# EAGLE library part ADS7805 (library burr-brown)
16-Bit 10us Sampling CMOS ADC

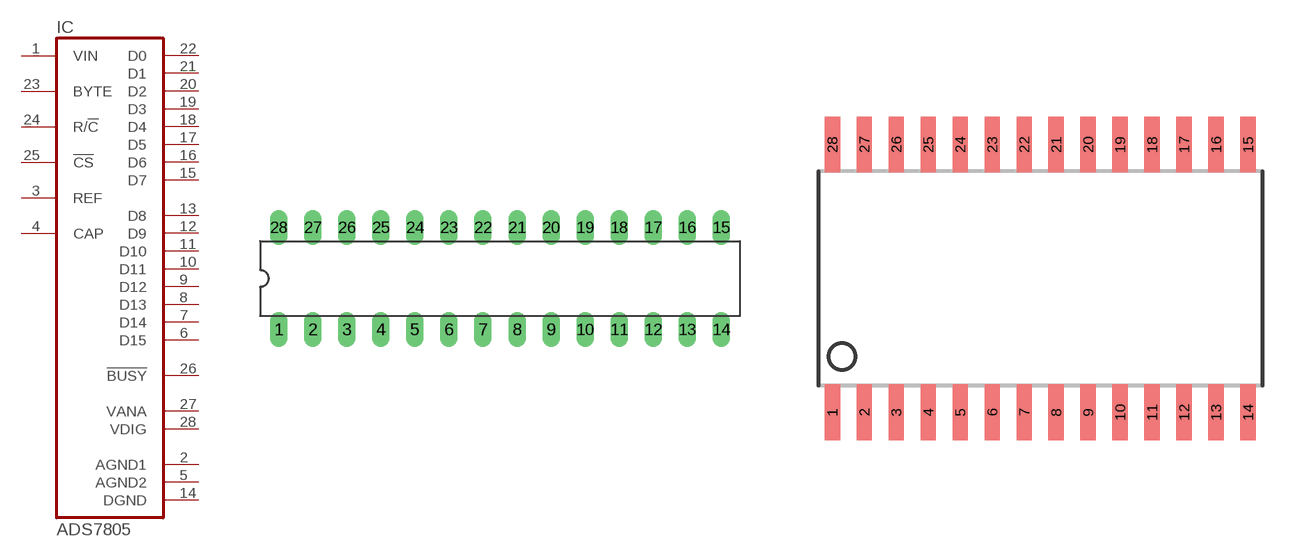
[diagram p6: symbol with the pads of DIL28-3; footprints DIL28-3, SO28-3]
Designator prefix IC

## ADS7805P (MF: TEXAS INSTRUMENTS; MPN: ADS7805P; OC_FARNELL: 1212283; OC_NEWARK: 35C1528)  [DIL28-3]
1  VIN  in
2  AGND1  pwr
3  REF
4  CAP  pas
5  AGND2  pwr
6  D15  out
7  D14  out
8  D13  out
9  D12  out
10  D11  out
11  D10  out
12  D9  out
13  D8  out
14  DGND  pwr
15  D7  out
16  D6  out
17  D5  out
18  D4  out
19  D3  out
20  D2  out
21  D1  out
22  D0  out
23  BYTE  in
24  R/!C  in
25  !CS  in
26  !BUSY  out
27  VANA  pwr
28  VDIG  pwr

## ADS7805U (MF: TEXAS INSTRUMENTS; MPN: ADS7805U; OC_FARNELL: 1192284; OC_NEWARK: 80K5546)  [SO28-3]
Pads as for DIL28-3

## Footprint DIL28-3 (pad centres in mm)
Dual In Line 0.3 inch
drill 0.813 long: 1 -16.51,-3.81; 2 -13.97,-3.81; 3 -11.43,-3.81; 4 -8.89,-3.81; 5 -6.35,-3.81; 6 -3.81,-3.81; 7 -1.27,-3.81; 8 1.27,-3.81; 9 3.81,-3.81; 10 6.35,-3.81; 11 8.89,-3.81; 12 11.43,-3.81; 13 13.97,-3.81; 14 16.51,-3.81; 15 16.51,3.81; 16 13.97,3.81; 17 11.43,3.81; 18 8.89,3.81; 19 6.35,3.81; 20 3.81,3.81; 21 1.27,3.81; 22 -1.27,3.81; 23 -3.81,3.81; 24 -6.35,3.81; 25 -8.89,3.81; 26 -11.43,3.81; 27 -13.97,3.81; 28 -16.51,3.81

## Footprint SO28-3 (pad centres in mm)
Small Outline Package
smd 0.61 x 2.21: 1 -8.255,-5.315; 2 -6.985,-5.315; 3 -5.715,-5.315; 4 -4.445,-5.315; 5 -3.175,-5.315; 6 -1.905,-5.315; 7 -0.635,-5.315; 8 0.635,-5.315; 9 1.905,-5.315; 10 3.175,-5.315; 11 4.445,-5.315; 12 5.715,-5.315; 13 6.985,-5.315; 14 8.255,-5.315; 15 8.255,5.315; 16 6.985,5.315; 17 5.715,5.315; 18 4.445,5.315; 19 3.175,5.315; 20 1.905,5.315; 21 0.635,5.315; 22 -0.635,5.315; 23 -1.905,5.315; 24 -3.175,5.315; 25 -4.445,5.315; 26 -5.715,5.315; 27 -6.985,5.315; 28 -8.255,5.315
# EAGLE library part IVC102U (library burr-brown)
Amplifier Precision Switched Integrator Transimpedance

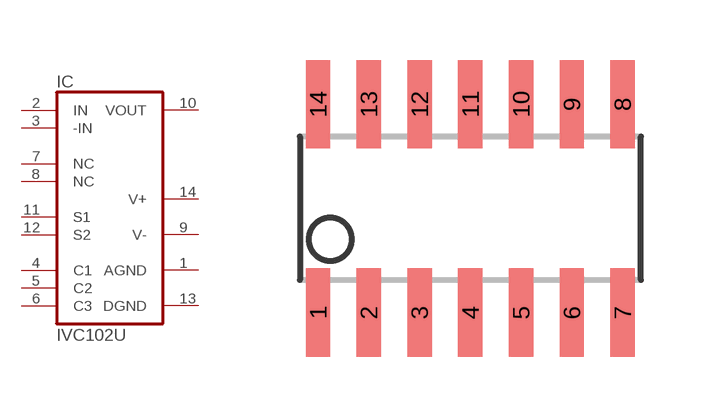
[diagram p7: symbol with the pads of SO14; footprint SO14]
Designator prefix IC

## IVC102U (MPN: IVC102U; OC_FARNELL: 1212427; OC_NEWARK: 03P0868)  [SO14]
1  AGND  pwr
2  IN  in
3  -IN  in
4  C1  pas
5  C2  pas
6  C3  pas
7  NC  nc
8  NC  nc
9  V-  pwr
10  VOUT  out
11  S1  in
12  S2  in
13  DGND  pwr
14  V+  pwr

## Footprint SO14 (pad centres in mm)
Small Outline Package
smd 0.61 x 2.21: 1 -3.81,-2.603; 2 -2.54,-2.603; 3 -1.27,-2.603; 4 0,-2.603; 5 1.27,-2.603; 6 2.54,-2.603; 7 3.81,-2.603; 8 3.81,2.603; 9 2.54,2.603; 10 1.27,2.603; 11 0,2.603; 12 -1.27,2.603; 13 -2.54,2.603; 14 -3.81,2.603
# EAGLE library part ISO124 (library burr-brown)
Isolation Amplifier Precision, Lowest Cost

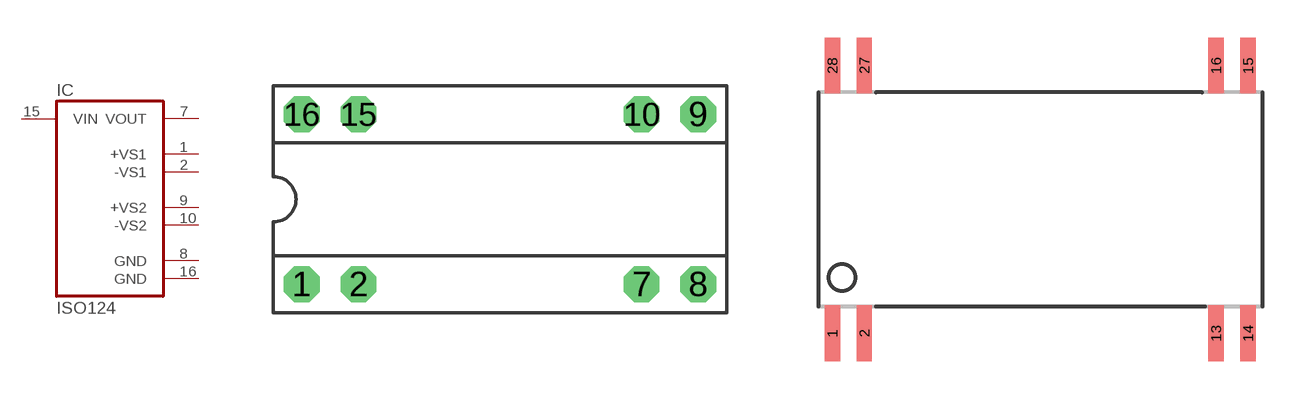
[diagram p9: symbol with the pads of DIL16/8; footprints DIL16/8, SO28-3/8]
Designator prefix IC

## ISO124P (MF: TEXAS INSTRUMENTS; MPN: ISO124P; OC_FARNELL: 1212425; OC_NEWARK: 35C1752)  [DIL16/8]
1  +VS1  pwr
2  -VS1  pwr
7  VOUT  out
8  GND  pwr
9  +VS2  pwr
10  -VS2  pwr
15  VIN  in
16  GND  pwr

## ISO124U (MF: TEXAS INSTRUMENTS; MPN: ISO124U; OC_FARNELL: 1212426; OC_NEWARK: 10M8426)  [SO28-3/8]
1  +VS1  pwr
2  -VS1  pwr
13  VOUT  out
14  GND  pwr
15  +VS2  pwr
16  -VS2  pwr
27  VIN  in
28  GND  pwr

## Footprint DIL16/8 (pad centres in mm)
Dual In Line
drill 0.813 pad 1.6 octagon: 1 -8.89,-3.81; 2 -6.35,-3.81; 7 6.35,-3.81; 8 8.89,-3.81; 9 8.89,3.81; 10 6.35,3.81; 15 -6.35,3.81; 16 -8.89,3.81

## Footprint SO28-3/8 (pad centres in mm)
Small Outline Package
smd 0.61 x 2.21: 1 -8.255,-5.315; 2 -6.985,-5.315; 13 6.985,-5.315; 14 8.255,-5.315; 15 8.255,5.315; 16 6.985,5.315; 27 -6.985,5.315; 28 -8.255,5.315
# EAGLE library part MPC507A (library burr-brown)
CMOS Analog Multiplexers Single-Ended 16-Channel/Differential 8-Channel

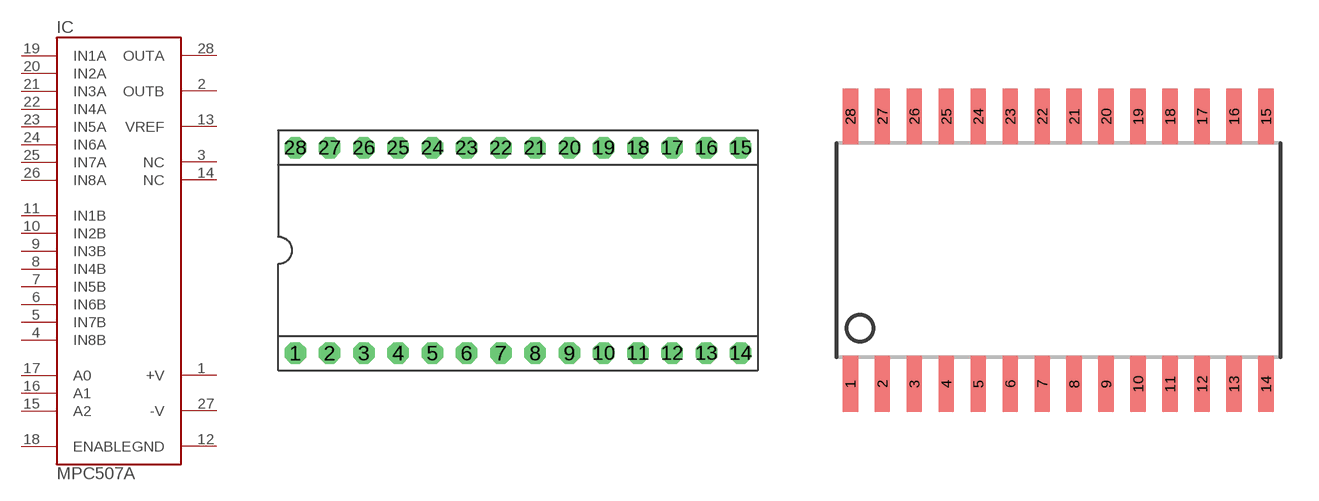
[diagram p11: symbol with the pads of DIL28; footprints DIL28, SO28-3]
Designator prefix IC

## MPC507AP (MF: TEXAS INSTRUMENTS; MPN: MPC507AP; OC_FARNELL: 1648762; OC_NEWARK: 75C3662)  [DIL28]
1  +V  pwr
2  OUTB  out
3  NC  nc
4  IN8B  in
5  IN7B  in
6  IN6B  in
7  IN5B  in
8  IN4B  in
9  IN3B  in
10  IN2B  in
11  IN1B  in
12  GND  pwr
13  VREF
14  NC  nc
15  A2  in
16  A1  in
17  A0  in
18  ENABLE  in
19  IN1A  in
20  IN2A  in
21  IN3A  in
22  IN4A  in
23  IN5A  in
24  IN6A  in
25  IN7A  in
26  IN8A  in
27  -V  pwr
28  OUTA  out

## MPC507AU (MF: TEXAS INSTRUMENTS; MPN: MPC507AU; OC_FARNELL: 1577157; OC_NEWARK: 75C3663)  [SO28-3]
Pads as for DIL28

## Footprint DIL28 (pad centres in mm)
Dual In Line
drill 0.813 pad 1.6 octagon: 1 -16.51,-7.62; 2 -13.97,-7.62; 3 -11.43,-7.62; 4 -8.89,-7.62; 5 -6.35,-7.62; 6 -3.81,-7.62; 7 -1.27,-7.62; 8 1.27,-7.62; 9 3.81,-7.62; 10 6.35,-7.62; 11 8.89,-7.62; 12 11.43,-7.62; 13 13.97,-7.62; 14 16.51,-7.62; 15 16.51,7.62; 16 13.97,7.62; 17 11.43,7.62; 18 8.89,7.62; 19 6.35,7.62; 20 3.81,7.62; 21 1.27,7.62; 22 -1.27,7.62; 23 -3.81,7.62; 24 -6.35,7.62; 25 -8.89,7.62; 26 -11.43,7.62; 27 -13.97,7.62; 28 -16.51,7.62

## Footprint SO28-3 (pad centres in mm)
Small Outline Package
smd 0.61 x 2.21: 1 -8.255,-5.315; 2 -6.985,-5.315; 3 -5.715,-5.315; 4 -4.445,-5.315; 5 -3.175,-5.315; 6 -1.905,-5.315; 7 -0.635,-5.315; 8 0.635,-5.315; 9 1.905,-5.315; 10 3.175,-5.315; 11 4.445,-5.315; 12 5.715,-5.315; 13 6.985,-5.315; 14 8.255,-5.315; 15 8.255,5.315; 16 6.985,5.315; 17 5.715,5.315; 18 4.445,5.315; 19 3.175,5.315; 20 1.905,5.315; 21 0.635,5.315; 22 -0.635,5.315; 23 -1.905,5.315; 24 -3.175,5.315; 25 -4.445,5.315; 26 -5.715,5.315; 27 -6.985,5.315; 28 -8.255,5.315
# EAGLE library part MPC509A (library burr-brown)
CMOS Analog Multiplexers Single-Ended 8-Channel/Differential 4-Channel

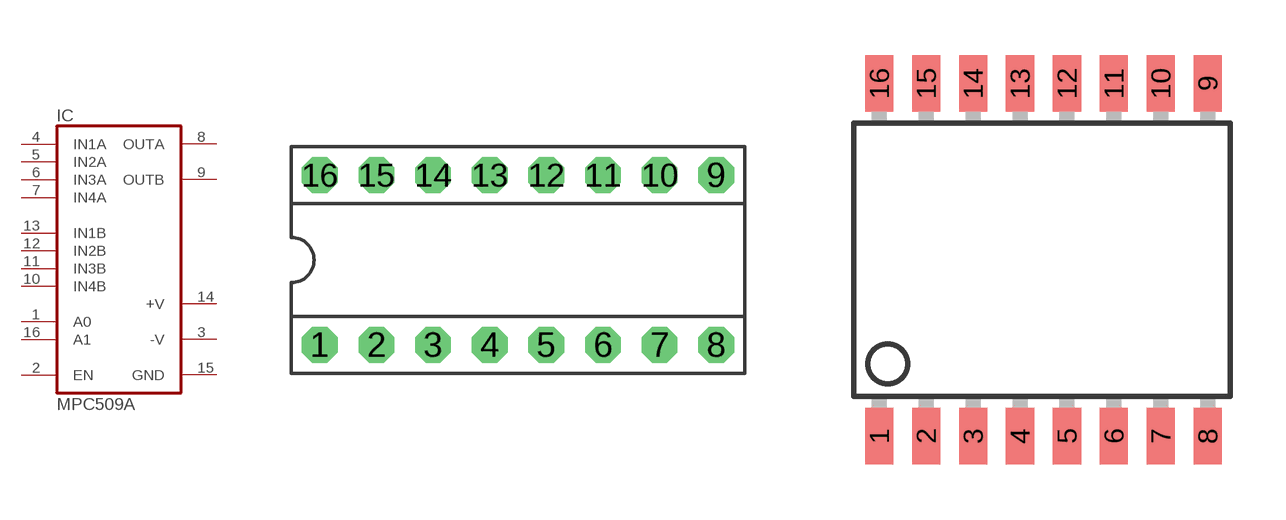
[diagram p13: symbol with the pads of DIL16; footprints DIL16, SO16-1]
Designator prefix IC

## MPC509AP (MF: TEXAS INSTRUMENT CONNECTORS; MPN: MPC509AP; OC_FARNELL: 1214449; OC_NEWARK: 75C3667)  [DIL16]
1  A0  in
2  EN  in
3  -V  pwr
4  IN1A  in
5  IN2A  in
6  IN3A  in
7  IN4A  in
8  OUTA  out
9  OUTB  out
10  IN4B  in
11  IN3B  in
12  IN2B  in
13  IN1B  in
14  +V  pwr
15  GND  pwr
16  A1  in

## MPC509AU (MPN: MPC509AUG4; OC_FARNELL: 1206921; OC_NEWARK: 97K5354)  [SO16-1]
Pads as for DIL16

## Footprint DIL16 (pad centres in mm)
Dual In Line
drill 0.813 pad 1.6 octagon: 1 -8.89,-3.81; 2 -6.35,-3.81; 3 -3.81,-3.81; 4 -1.27,-3.81; 5 1.27,-3.81; 6 3.81,-3.81; 7 6.35,-3.81; 8 8.89,-3.81; 9 8.89,3.81; 10 6.35,3.81; 11 3.81,3.81; 12 1.27,3.81; 13 -1.27,3.81; 14 -3.81,3.81; 15 -6.35,3.81; 16 -8.89,3.81

## Footprint SO16-1 (pad centres in mm)
Small Outline Package
smd 0.762 x 1.524: 1 -4.445,-4.775; 2 -3.175,-4.775; 3 -1.905,-4.775; 4 -0.635,-4.775; 5 0.635,-4.775; 6 1.905,-4.775; 7 3.175,-4.775; 8 4.445,-4.775; 9 4.445,4.775; 10 3.175,4.775; 11 1.905,4.775; 12 0.635,4.775; 13 -0.635,4.775; 14 -1.905,4.775; 15 -3.175,4.775; 16 -4.445,4.775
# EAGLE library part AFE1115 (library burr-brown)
HDSL/MDSL Analog Front End with VCXO

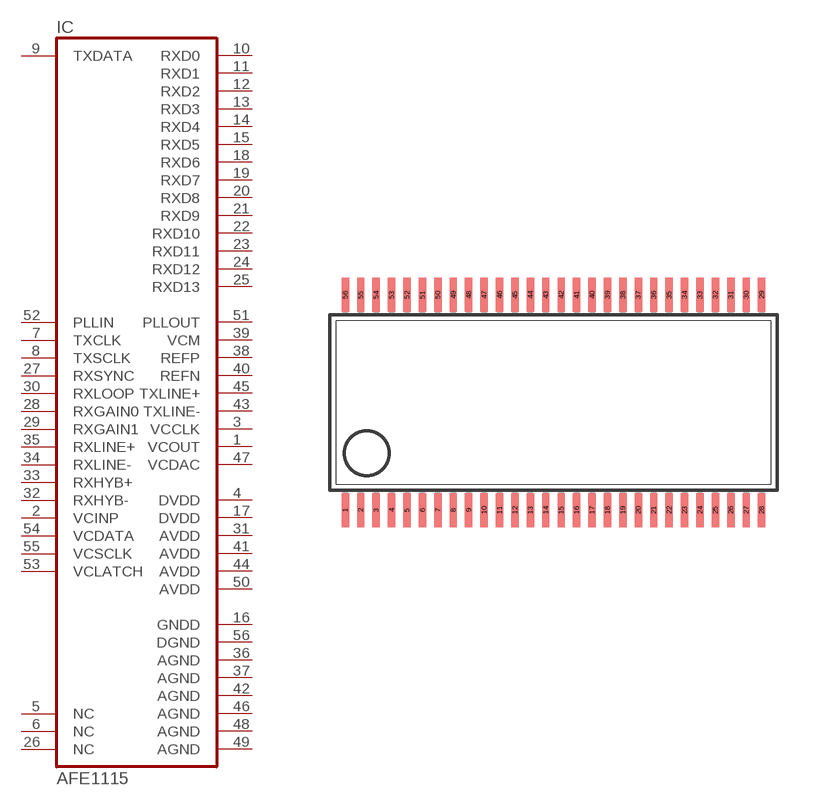
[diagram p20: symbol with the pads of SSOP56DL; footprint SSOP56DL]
Designator prefix IC

## AFE1115E (OC_FARNELL: unknown; OC_NEWARK: unknown)  [SSOP56DL]
1  VCOUT  out
2  VCINP  in
3  VCCLK  out
4  DVDD  pwr
5  NC  nc
6  NC  nc
7  TXCLK  in
8  TXSCLK  in
9  TXDATA  in
10  RXD0  out
11  RXD1  out
12  RXD2  out
13  RXD3  out
14  RXD4  out
15  RXD5  out
16  GNDD  pwr
17  DVDD  pwr
18  RXD6  out
19  RXD7  out
20  RXD8  out
21  RXD9  out
22  RXD10  out
23  RXD11  out
24  RXD12  out
25  RXD13  out
26  NC  nc
27  RXSYNC  in
28  RXGAIN0  in
29  RXGAIN1  in
30  RXLOOP  in
31  AVDD  pwr
32  RXHYB-  in
33  RXHYB+  in
34  RXLINE-  in
35  RXLINE+  in
36  AGND  pwr
37  AGND  pwr
38  REFP  out
39  VCM  out
40  REFN  out
41  AVDD  pwr
42  AGND  pwr
43  TXLINE-  out
44  AVDD  pwr
45  TXLINE+  out
46  AGND  pwr
47  VCDAC  out
48  AGND  pwr
49  AGND  out
50  AVDD  pwr
51  PLLOUT  out
52  PLLIN  in
53  VCLATCH  in
54  VCDATA  in
55  VCSCLK  in
56  DGND  pwr

## Footprint SSOP56DL (pad centres in mm)
Small Shrink Outline Package
smd 0.305 x 1.397: 1 -8.572,-4.432; 2 -7.938,-4.432; 3 -7.303,-4.432; 4 -6.668,-4.432; 5 -6.032,-4.432; 6 -5.397,-4.432; 7 -4.763,-4.432; 8 -4.128,-4.432; 9 -3.493,-4.432; 10 -2.857,-4.432; 11 -2.223,-4.432; 12 -1.587,-4.432; 13 -0.953,-4.432; 14 -0.318,-4.432; 15 0.318,-4.432; 16 0.953,-4.432; 17 1.587,-4.432; 18 2.223,-4.432; 19 2.857,-4.432; 20 3.493,-4.432; 21 4.128,-4.432; 22 4.763,-4.432; 23 5.397,-4.432; 24 6.032,-4.432; 25 6.668,-4.432; 26 7.303,-4.432; 27 7.938,-4.432; 28 8.572,-4.432; 29 8.572,4.432; 30 7.938,4.432; 31 7.303,4.432; 32 6.668,4.432; 33 6.032,4.432; 34 5.397,4.432; 35 4.763,4.432; 36 4.128,4.432; 37 3.493,4.432; 38 2.857,4.432; 39 2.223,4.432; 40 1.587,4.432; 41 0.953,4.432; 42 0.318,4.432; 43 -0.318,4.432; 44 -0.953,4.432; 45 -1.587,4.432; 46 -2.223,4.432; 47 -2.857,4.432; 48 -3.493,4.432; 49 -4.128,4.432; 50 -4.763,4.432; 51 -5.397,4.432; 52 -6.032,4.432; 53 -6.668,4.432; 54 -7.303,4.432; 55 -7.938,4.432; 56 -8.572,4.432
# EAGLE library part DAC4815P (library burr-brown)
Quad 12-Bit DAC 8-Bit Port Interface

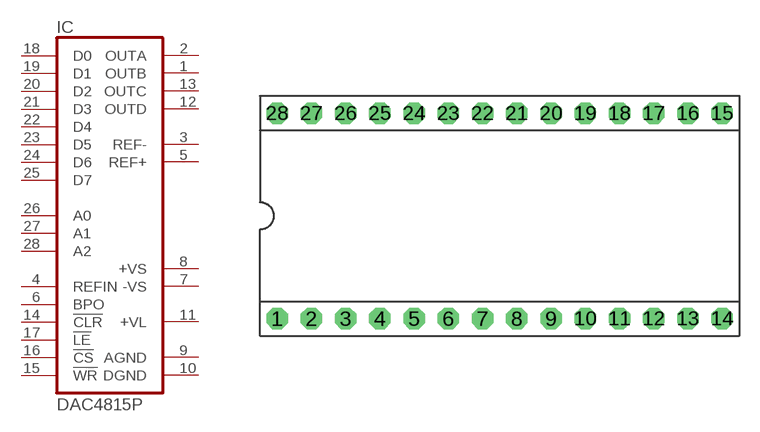
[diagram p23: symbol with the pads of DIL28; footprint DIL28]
Designator prefix IC

## DAC4815PP (OC_FARNELL: unknown; OC_NEWARK: unknown)  [DIL28]
1  OUTB  out
2  OUTA  out
3  REF-  out
4  REFIN  in
5  REF+  out
6  BPO  in
7  -VS  pwr
8  +VS  pwr
9  AGND  pwr
10  DGND  pwr
11  +VL  pwr
12  OUTD  out
13  OUTC  out
14  !CLR  in
15  !WR  in
16  !CS  in
17  !LE  in
18  D0  in
19  D1  in
20  D2  in
21  D3  in
22  D4  in
23  D5  in
24  D6  in
25  D7  in
26  A0  in
27  A1  in
28  A2  in

## Footprint DIL28 (pad centres in mm)
Dual In Line
drill 0.813 pad 1.6 octagon: 1 -16.51,-7.62; 2 -13.97,-7.62; 3 -11.43,-7.62; 4 -8.89,-7.62; 5 -6.35,-7.62; 6 -3.81,-7.62; 7 -1.27,-7.62; 8 1.27,-7.62; 9 3.81,-7.62; 10 6.35,-7.62; 11 8.89,-7.62; 12 11.43,-7.62; 13 13.97,-7.62; 14 16.51,-7.62; 15 16.51,7.62; 16 13.97,7.62; 17 11.43,7.62; 18 8.89,7.62; 19 6.35,7.62; 20 3.81,7.62; 21 1.27,7.62; 22 -1.27,7.62; 23 -3.81,7.62; 24 -6.35,7.62; 25 -8.89,7.62; 26 -11.43,7.62; 27 -13.97,7.62; 28 -16.51,7.62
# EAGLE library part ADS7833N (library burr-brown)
10-Channel, 12-Bit Data Acquisition System three synchronized A/D converters and seven S/H amplifiers

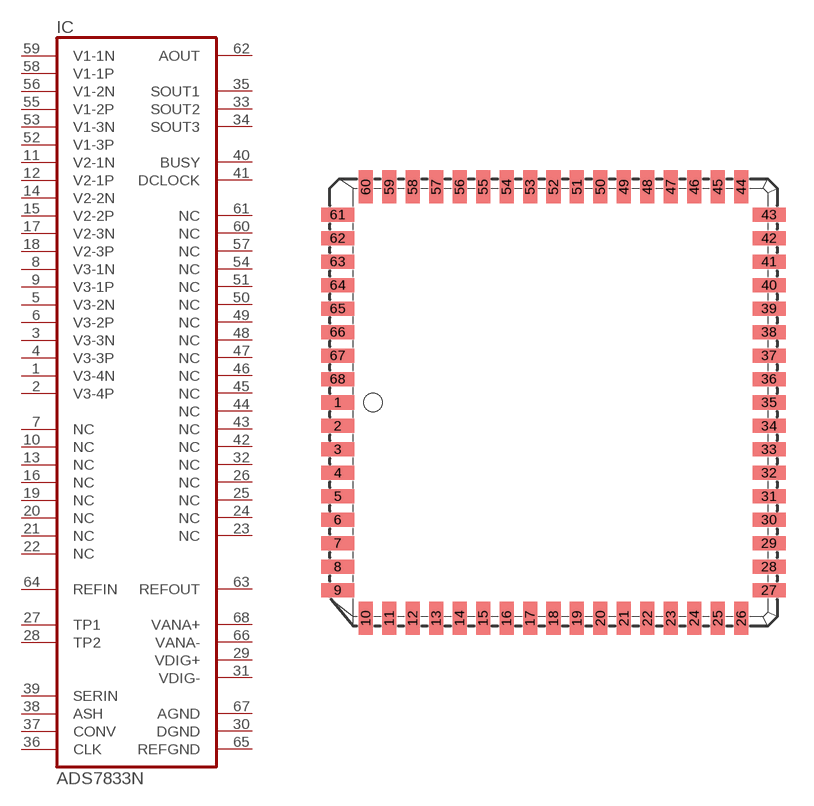
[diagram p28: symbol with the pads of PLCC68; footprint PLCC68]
Designator prefix IC

## ADS7833N (OC_FARNELL: unknown; OC_NEWARK: unknown)  [PLCC68]
1  V3-4N  in
2  V3-4P  in
3  V3-3N  in
4  V3-3P  in
5  V3-2N  in
6  V3-2P  in
7  NC  nc
8  V3-1N  in
9  V3-1P  in
10  NC  nc
11  V2-1N  in
12  V2-1P  in
13  NC  nc
14  V2-2N  in
15  V2-2P  in
16  NC  nc
17  V2-3N  in
18  V2-3P  in
19  NC  nc
20  NC  nc
21  NC  nc
22  NC  nc
23  NC  nc
24  NC  nc
25  NC  nc
26  NC  nc
27  TP1  pas
28  TP2  pas
29  VDIG+  pwr
30  DGND  pwr
31  VDIG-  pwr
32  NC  nc
33  SOUT2  out
34  SOUT3  out
35  SOUT1  out
36  CLK  in
37  CONV  in
38  ASH  in
39  SERIN  in
40  BUSY  out
41  DCLOCK  out
42  NC  nc
43  NC  nc
44  NC  nc
45  NC  nc
46  NC  nc
47  NC  nc
48  NC  nc
49  NC  nc
50  NC  nc
51  NC  nc
52  V1-3P  in
53  V1-3N  in
54  NC  nc
55  V1-2P  in
56  V1-2N  in
57  NC  nc
58  V1-1P  in
59  V1-1N  in
60  NC  nc
61  NC  nc
62  AOUT  out
63  REFOUT  out
64  REFIN  in
65  REFGND  pwr
66  VANA-  pwr
67  AGND  pwr
68  VANA+  pwr

## Footprint PLCC68 (pad centres in mm)
PLASTIC LEADED CHIP CARRIER square
smd 1.8 x 0.76: 1 -11.67,0; 2 -11.67,-1.27; 3 -11.67,-2.54; 4 -11.67,-3.81; 5 -11.67,-5.08; 6 -11.67,-6.35; 7 -11.67,-7.62; 8 -11.67,-8.89; 9 -11.67,-10.16; 27 11.67,-10.16; 28 11.67,-8.89; 29 11.67,-7.62; 30 11.67,-6.35; 31 11.67,-5.08; 32 11.67,-3.81; 33 11.67,-2.54; 34 11.67,-1.27; 35 11.67,0; 36 11.67,1.27; 37 11.67,2.54; 38 11.67,3.81; 39 11.67,5.08; 40 11.67,6.35; 41 11.67,7.62; 42 11.67,8.89; 43 11.67,10.16; 61 -11.67,10.16; 62 -11.67,8.89; 63 -11.67,7.62; 64 -11.67,6.35; 65 -11.67,5.08; 66 -11.67,3.81; 67 -11.67,2.54; 68 -11.67,1.27
smd 0.76 x 1.8: 10 -10.16,-11.67; 11 -8.89,-11.67; 12 -7.62,-11.67; 13 -6.35,-11.67; 14 -5.08,-11.67; 15 -3.81,-11.67; 16 -2.54,-11.67; 17 -1.27,-11.67; 18 0,-11.67; 19 1.27,-11.67; 20 2.54,-11.67; 21 3.81,-11.67; 22 5.08,-11.67; 23 6.35,-11.67; 24 7.62,-11.67; 25 8.89,-11.67; 26 10.16,-11.67; 44 10.16,11.67; 45 8.89,11.67; 46 7.62,11.67; 47 6.35,11.67; 48 5.08,11.67; 49 3.81,11.67; 50 2.54,11.67; 51 1.27,11.67; 52 0,11.67; 53 -1.27,11.67; 54 -2.54,11.67; 55 -3.81,11.67; 56 -5.08,11.67; 57 -6.35,11.67; 58 -7.62,11.67; 59 -8.89,11.67; 60 -10.16,11.67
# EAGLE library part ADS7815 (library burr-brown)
16-Bit 250kHz Sampling CMOS ADC

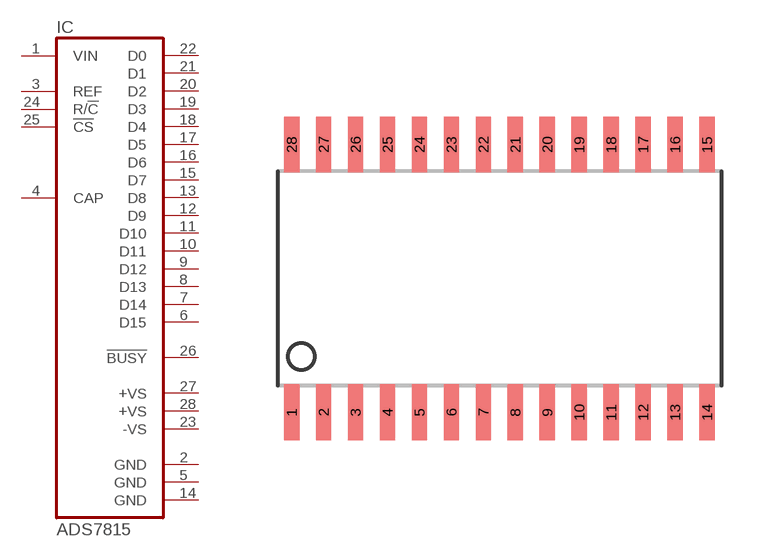
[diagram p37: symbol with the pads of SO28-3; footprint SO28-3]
Designator prefix IC

## ADS7815U (MPN: ADS7815UE4; OC_FARNELL: 1206867; OC_NEWARK: 96K6229)  [SO28-3]
1  VIN  in
2  GND  pwr
3  REF
4  CAP  pas
5  GND  pwr
6  D15  pwr
7  D14  pwr
8  D13  pwr
9  D12  pwr
10  D11  out
11  D10  out
12  D9  out
13  D8  out
14  GND  pwr
15  D7  out
16  D6  out
17  D5  out
18  D4  out
19  D3  out
20  D2  out
21  D1  out
22  D0  out
23  -VS  pwr
24  R/!C  in
25  !CS  in
26  !BUSY  out
27  +VS  pwr
28  +VS  pwr

## Footprint SO28-3 (pad centres in mm)
Small Outline Package
smd 0.61 x 2.21: 1 -8.255,-5.315; 2 -6.985,-5.315; 3 -5.715,-5.315; 4 -4.445,-5.315; 5 -3.175,-5.315; 6 -1.905,-5.315; 7 -0.635,-5.315; 8 0.635,-5.315; 9 1.905,-5.315; 10 3.175,-5.315; 11 4.445,-5.315; 12 5.715,-5.315; 13 6.985,-5.315; 14 8.255,-5.315; 15 8.255,5.315; 16 6.985,5.315; 17 5.715,5.315; 18 4.445,5.315; 19 3.175,5.315; 20 1.905,5.315; 21 0.635,5.315; 22 -0.635,5.315; 23 -1.905,5.315; 24 -3.175,5.315; 25 -4.445,5.315; 26 -5.715,5.315; 27 -6.985,5.315; 28 -8.255,5.315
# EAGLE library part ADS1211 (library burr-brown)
24-Bit Analog-to-Digital Converter

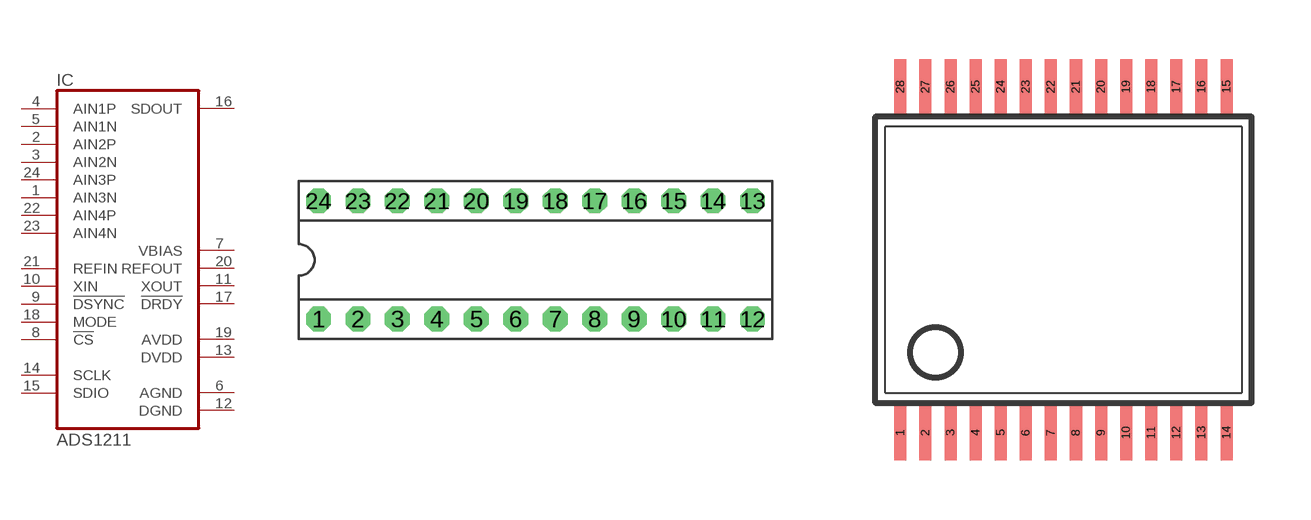
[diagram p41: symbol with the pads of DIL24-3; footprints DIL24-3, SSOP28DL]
Designator prefix IC

## ADS1211P (MF: TEXAS INSTRUMENTS; MPN: ADS1211P; OC_FARNELL: 1219430; OC_NEWARK: 96K2329)  [DIL24-3]
1  AIN3N  in
2  AIN2P  in
3  AIN2N  in
4  AIN1P  in
5  AIN1N  in
6  AGND  pwr
7  VBIAS  out
8  !CS  in
9  !DSYNC  in
10  XIN  in
11  XOUT  out
12  DGND  pwr
13  DVDD  pwr
14  SCLK
15  SDIO
16  SDOUT  out
17  !DRDY  out
18  MODE  in
19  AVDD  pwr
20  REFOUT  out
21  REFIN  in
22  AIN4P  in
23  AIN4N  in
24  AIN3P  in

## ADS1211E (MF: TEXAS INSTRUMENT CONNECTORS; MPN: ADS1211E; OC_FARNELL: unknown; OC_NEWARK: 74C6976)  [SSOP28DL]
1  AIN3N  in
2  AIN2P  in
3  AIN2N  in
4  AIN1P  in
5  AIN1N  in
6  AGND  pwr
7  VBIAS  out
10  !CS  in
11  !DSYNC  in
12  XIN  in
13  XOUT  out
14  DGND  pwr
15  DVDD  pwr
16  SCLK
17  SDIO
18  SDOUT  out
19  !DRDY  out
22  MODE  in
23  AVDD  pwr
24  REFOUT  out
25  REFIN  in
26  AIN4P  in
27  AIN4N  in
28  AIN3P  in

## ADS1211U (MF: FARNELL; MPN: ADS1211U..; OC_FARNELL: 9324070; OC_NEWARK: 37K8944)  [SO24L]
Pads as for DIL24-3

## Footprint DIL24-3 (pad centres in mm)
Dual In Line 0.3 inch
drill 0.813 pad 1.6 octagon: 1 -13.97,-3.81; 2 -11.43,-3.81; 3 -8.89,-3.81; 4 -6.35,-3.81; 5 -3.81,-3.81; 6 -1.27,-3.81; 7 1.27,-3.81; 8 3.81,-3.81; 9 6.35,-3.81; 10 8.89,-3.81; 11 11.43,-3.81; 12 13.97,-3.81; 13 13.97,3.81; 14 11.43,3.81; 15 8.89,3.81; 16 6.35,3.81; 17 3.81,3.81; 18 1.27,3.81; 19 -1.27,3.81; 20 -3.81,3.81; 21 -6.35,3.81; 22 -8.89,3.81; 23 -11.43,3.81; 24 -13.97,3.81

## Footprint SSOP28DL (pad centres in mm)
Small Shrink Outline Package
smd 0.305 x 1.397: 1 -4.128,-4.381; 2 -3.493,-4.381; 3 -2.857,-4.381; 4 -2.223,-4.381; 5 -1.587,-4.381; 6 -0.953,-4.381; 7 -0.318,-4.381; 8 0.318,-4.381; 9 0.953,-4.381; 10 1.587,-4.381; 11 2.223,-4.381; 12 2.857,-4.381; 13 3.493,-4.381; 14 4.128,-4.381; 15 4.128,4.381; 16 3.493,4.381; 17 2.857,4.381; 18 2.223,4.381; 19 1.587,4.381; 20 0.953,4.381; 21 0.318,4.381; 22 -0.318,4.381; 23 -0.953,4.381; 24 -1.587,4.381; 25 -2.223,4.381; 26 -2.857,4.381; 27 -3.493,4.381; 28 -4.128,4.381

## Footprint SO24L (pad centres in mm)
Small Outline Package, large
smd 0.61 x 2.21: 1 -6.985,-5.029; 2 -5.715,-5.029; 3 -4.445,-5.029; 4 -3.175,-5.029; 5 -1.905,-5.029; 6 -0.635,-5.029; 7 0.635,-5.029; 8 1.905,-5.029; 9 3.175,-5.029; 10 4.445,-5.029; 11 5.715,-5.029; 12 6.985,-5.029; 13 6.985,5.029; 14 5.715,5.029; 15 4.445,5.029; 16 3.175,5.029; 17 1.905,5.029; 18 0.635,5.029; 19 -0.635,5.029; 20 -1.905,5.029; 21 -3.175,5.029; 22 -4.445,5.029; 23 -5.715,5.029; 24 -6.985,5.029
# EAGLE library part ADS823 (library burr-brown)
10-Bit, 60 MSPS ADC SE/Diff, Int/Ext Ref. program. i/p range w/Pwrdown

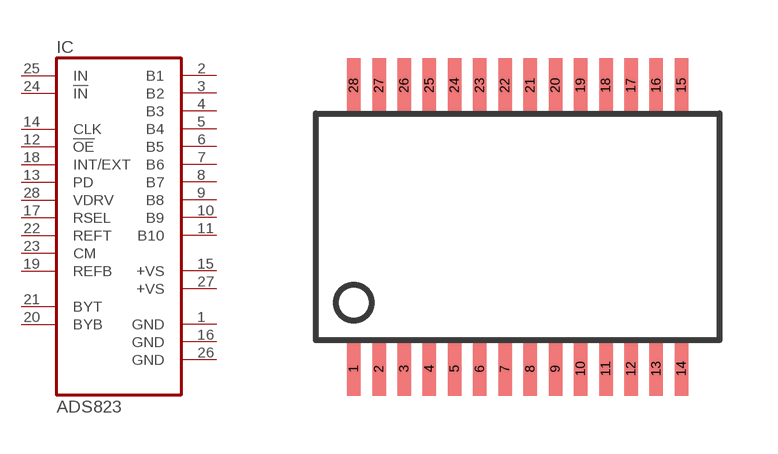
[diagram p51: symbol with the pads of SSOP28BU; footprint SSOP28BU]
Designator prefix IC

## ADS823E (MF: TEXAS INSTRUMENTS; MPN: ADS823E; OC_FARNELL: unknown; OC_NEWARK: 35C1576)  [SSOP28BU]
1  GND  pwr
2  B1  out
3  B2  out
4  B3  out
5  B4  out
6  B5  out
7  B6  out
8  B7  out
9  B8  out
10  B9  out
11  B10  out
12  !OE  in
13  PD  in
14  CLK  in
15  +VS  pwr
16  GND  pwr
17  RSEL  in
18  INT/EXT  in
19  REFB  in
20  BYB  pas
21  BYT  pas
22  REFT  in
23  CM  in
24  !IN  in
25  IN  in
26  GND  pwr
27  +VS  pwr
28  VDRV  in

## Footprint SSOP28BU (pad centres in mm)
Small Shrink Outline Package
smd 0.348 x 1.397: 1 -4.225,-3.656; 2 -3.575,-3.656; 3 -2.925,-3.656; 4 -2.275,-3.656; 5 -1.625,-3.656; 6 -0.975,-3.656; 7 -0.325,-3.656; 8 0.325,-3.656; 9 0.975,-3.656; 10 1.625,-3.656; 11 2.275,-3.656; 12 2.925,-3.656; 13 3.575,-3.656; 14 4.225,-3.656; 15 4.225,3.656; 16 3.575,3.656; 17 2.925,3.656; 18 2.275,3.656; 19 1.625,3.656; 20 0.975,3.656; 21 0.325,3.656; 22 -0.325,3.656; 23 -0.975,3.656; 24 -1.625,3.656; 25 -2.275,3.656; 26 -2.925,3.656; 27 -3.575,3.656; 28 -4.225,3.656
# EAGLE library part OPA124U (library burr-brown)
Difet Operational Amplifier

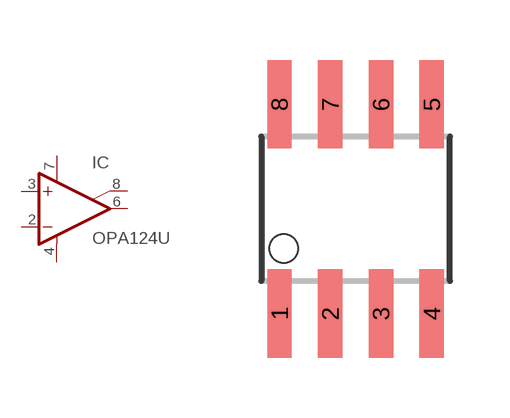
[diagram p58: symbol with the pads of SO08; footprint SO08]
Designator prefix IC

## OPA124U (MF: TEXAS INSTRUMENTS; MPN: OPA124U; OC_FARNELL: 1206923; OC_NEWARK: 80K6002)  [SO08]
2  -IN  in
3  +IN  in
4  V-  pwr
6  OUT  out
7  V+  pwr
8  SUBS  pas

## Footprint SO08 (pad centres in mm)
Small Outline Package
smd 0.61 x 2.21: 1 -1.905,-2.616; 2 -0.635,-2.616; 3 0.635,-2.616; 4 1.905,-2.616; 5 1.905,2.616; 6 0.635,2.616; 7 -0.635,2.616; 8 -1.905,2.616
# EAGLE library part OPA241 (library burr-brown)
Operational Amplifiers Single-Supply, MicroPower

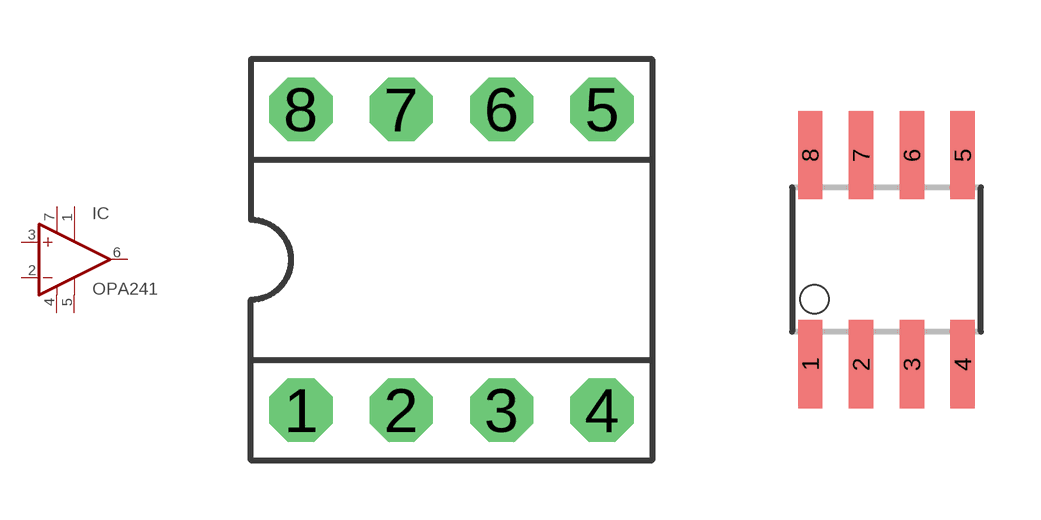
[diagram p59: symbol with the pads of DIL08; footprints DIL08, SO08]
Designator prefix IC

## OPA241P (MF: TEXAS INSTRUMENT CONNECTORS; MPN: OPA241PA; OC_FARNELL: 1097411; OC_NEWARK: 80K6022)  [DIL08]
1  TRIM1  pas
2  -IN  in
3  +IN  in
4  V-  pwr
5  TRIM2  pas
6  OUT  out
7  V+  pwr

## OPA241U (MF: TEXAS INSTRUMENTS; MPN: OPA241UA; OC_FARNELL: 1648699; OC_NEWARK: 75C4749)  [SO08]
Pads as for DIL08

## Footprint DIL08 (pad centres in mm)
Dual In Line
drill 0.813 pad 1.6 octagon: 1 -3.81,-3.81; 2 -1.27,-3.81; 3 1.27,-3.81; 4 3.81,-3.81; 5 3.81,3.81; 6 1.27,3.81; 7 -1.27,3.81; 8 -3.81,3.81

## Footprint SO08 (pad centres in mm)
Small Outline Package
smd 0.61 x 2.21: 1 -1.905,-2.616; 2 -0.635,-2.616; 3 0.635,-2.616; 4 1.905,-2.616; 5 1.905,2.616; 6 0.635,2.616; 7 -0.635,2.616; 8 -1.905,2.616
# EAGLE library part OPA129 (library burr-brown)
Difet Operational Amplifier Ultra-Low Bias Current

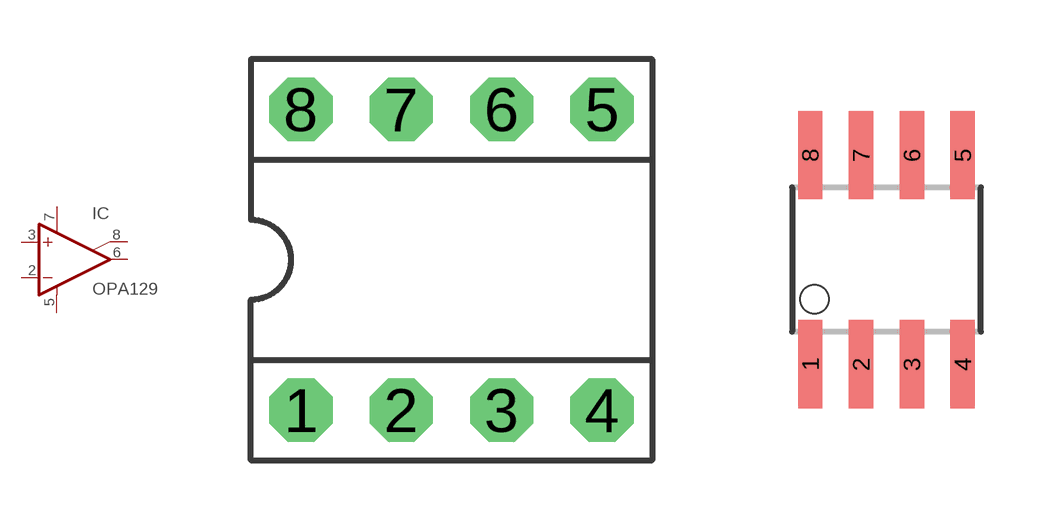
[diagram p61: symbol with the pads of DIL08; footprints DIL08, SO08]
Designator prefix IC

## OPA129P (OC_FARNELL: unknown; OC_NEWARK: unknown)  [DIL08]
2  -IN  in
3  +IN  in
5  V-  pwr
6  OUT  out
7  V+  pwr
8  SUBS  pas

## OPA129U (MF: TEXAS INSTRUMENTS; MPN: OPA129U; OC_FARNELL: 1206925; OC_NEWARK: 80K6004)  [SO08]
Pads as for DIL08

## Footprint DIL08 (pad centres in mm)
Dual In Line
drill 0.813 pad 1.6 octagon: 1 -3.81,-3.81; 2 -1.27,-3.81; 3 1.27,-3.81; 4 3.81,-3.81; 5 3.81,3.81; 6 1.27,3.81; 7 -1.27,3.81; 8 -3.81,3.81

## Footprint SO08 (pad centres in mm)
Small Outline Package
smd 0.61 x 2.21: 1 -1.905,-2.616; 2 -0.635,-2.616; 3 0.635,-2.616; 4 1.905,-2.616; 5 1.905,2.616; 6 0.635,2.616; 7 -0.635,2.616; 8 -1.905,2.616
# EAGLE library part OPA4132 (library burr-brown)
High Speed FET-Input Operational Amplifiers

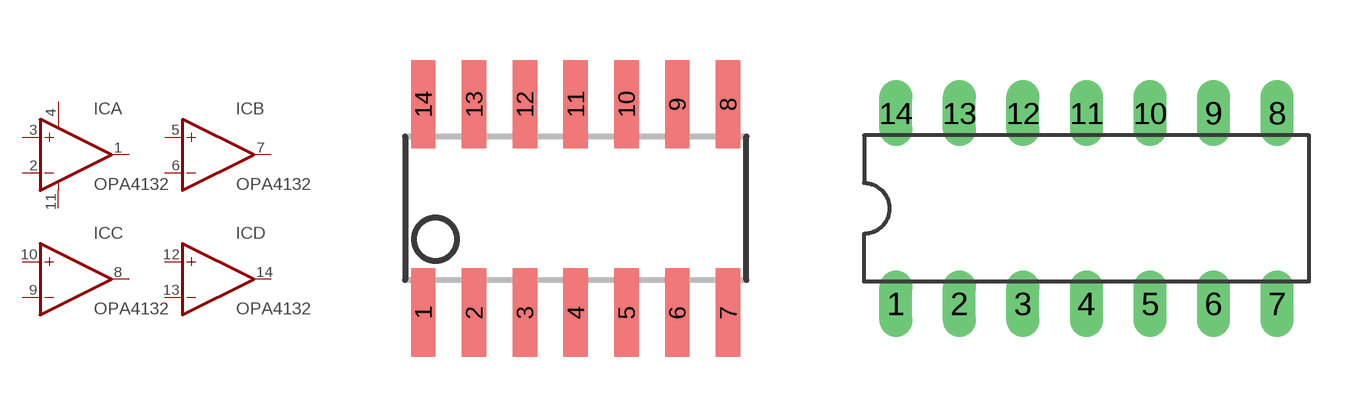
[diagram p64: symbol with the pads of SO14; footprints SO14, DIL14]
Designator prefix IC; gates A=OP-AMP+- B=OP-AMP C=OP-AMP D=OP-AMP

## OPA4132U (MF: TEXAS INSTRUMENTS; MPN: OPA4132UA; OC_FARNELL: 1212302; OC_NEWARK: 80K6028)  [SO14]
1  A:OUT  out
2  A:-IN  in
3  A:+IN  in
4  A:V+  pwr
5  B:+IN  in
6  B:-IN  in
7  B:OUT  out
8  C:OUT  out
9  C:-IN  in
10  C:+IN  in
11  A:V-  pwr
12  D:+IN  in
13  D:-IN  in
14  D:OUT  out

## OPA4132P (OC_FARNELL: unknown; OC_NEWARK: unknown)  [DIL14]
Pads as for SO14

## Footprint SO14 (pad centres in mm)
Small Outline Package
smd 0.61 x 2.21: 1 -3.81,-2.603; 2 -2.54,-2.603; 3 -1.27,-2.603; 4 0,-2.603; 5 1.27,-2.603; 6 2.54,-2.603; 7 3.81,-2.603; 8 3.81,2.603; 9 2.54,2.603; 10 1.27,2.603; 11 0,2.603; 12 -1.27,2.603; 13 -2.54,2.603; 14 -3.81,2.603

## Footprint DIL14 (pad centres in mm)
Dual In Line Package
drill 0.813 long: 1 -7.62,-3.81; 2 -5.08,-3.81; 3 -2.54,-3.81; 4 0,-3.81; 5 2.54,-3.81; 6 5.08,-3.81; 7 7.62,-3.81; 8 7.62,3.81; 9 5.08,3.81; 10 2.54,3.81; 11 0,3.81; 12 -2.54,3.81; 13 -5.08,3.81; 14 -7.62,3.81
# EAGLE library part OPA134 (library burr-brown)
Operational Amplifiers SoundPlus(TM) High Performance Audio

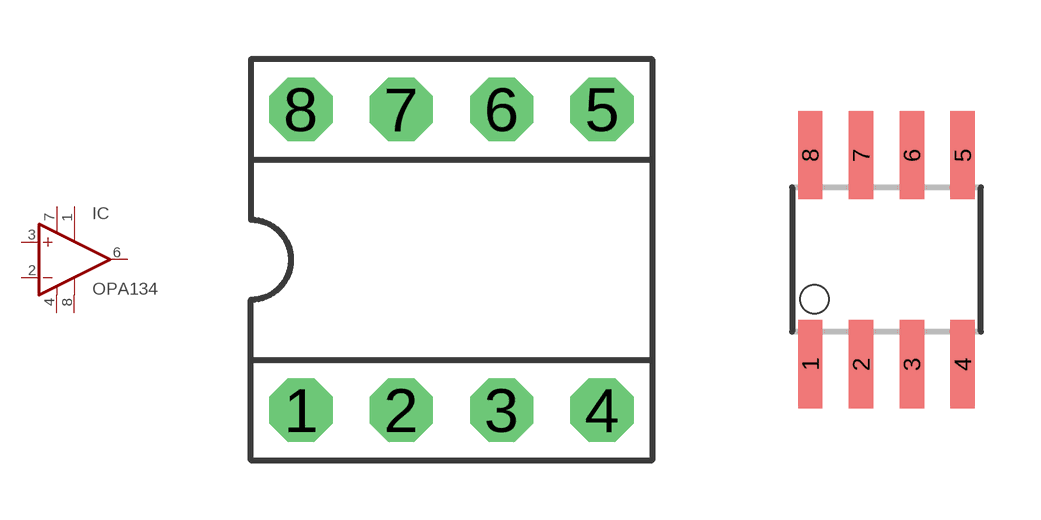
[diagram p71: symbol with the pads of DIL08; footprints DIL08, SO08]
Designator prefix IC

## OPA134P (MF: TEXAS INSTRUMENTS; MPN: OPA134PA; OC_FARNELL: 1335032; OC_NEWARK: 75C4599)  [DIL08]
1  TRIM1  pas
2  -IN  in
3  +IN  in
4  V-  pwr
6  OUT  out
7  V+  pwr
8  TRIM2  pas

## OPA134U (MF: TEXAS INSTRUMENTS; MPN: OPA134UA; OC_FARNELL: 1097514; OC_NEWARK: 80K6009)  [SO08]
Pads as for DIL08

## Footprint DIL08 (pad centres in mm)
Dual In Line
drill 0.813 pad 1.6 octagon: 1 -3.81,-3.81; 2 -1.27,-3.81; 3 1.27,-3.81; 4 3.81,-3.81; 5 3.81,3.81; 6 1.27,3.81; 7 -1.27,3.81; 8 -3.81,3.81

## Footprint SO08 (pad centres in mm)
Small Outline Package
smd 0.61 x 2.21: 1 -1.905,-2.616; 2 -0.635,-2.616; 3 0.635,-2.616; 4 1.905,-2.616; 5 1.905,2.616; 6 0.635,2.616; 7 -0.635,2.616; 8 -1.905,2.616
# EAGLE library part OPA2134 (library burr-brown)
Operational Amplifier

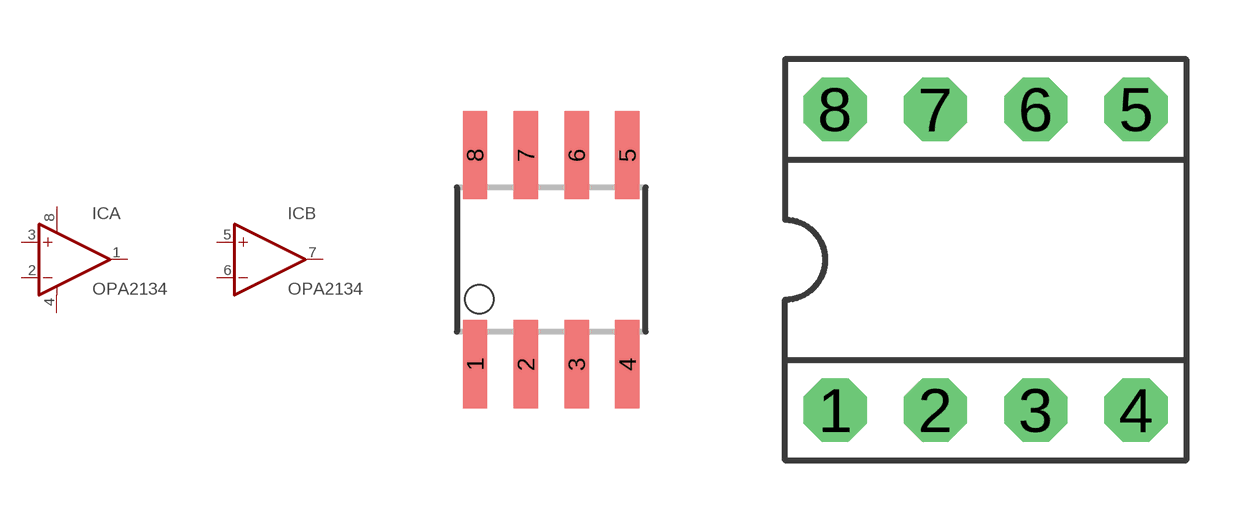
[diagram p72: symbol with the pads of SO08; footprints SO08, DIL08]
Designator prefix IC; gates A=OP-AMP+- B=OP-AMP

## OPA2134U (MF: TEXAS INSTRUMENTS; MPN: OPA2134UA; OC_FARNELL: 1206935; OC_NEWARK: 35C1847)  [SO08]
1  A:OUT  out
2  A:-IN  in
3  A:+IN  in
4  A:V-  pwr
5  B:+IN  in
6  B:-IN  in
7  B:OUT  out
8  A:V+  pwr

## OPA2134P (MF: TEXAS INSTRUMENTS; MPN: OPA2134PA; OC_FARNELL: 1097574; OC_NEWARK: 74K3897)  [DIL08]
Pads as for SO08

## Footprint SO08 (pad centres in mm)
Small Outline Package
smd 0.61 x 2.21: 1 -1.905,-2.616; 2 -0.635,-2.616; 3 0.635,-2.616; 4 1.905,-2.616; 5 1.905,2.616; 6 0.635,2.616; 7 -0.635,2.616; 8 -1.905,2.616

## Footprint DIL08 (pad centres in mm)
Dual In Line
drill 0.813 pad 1.6 octagon: 1 -3.81,-3.81; 2 -1.27,-3.81; 3 1.27,-3.81; 4 3.81,-3.81; 5 3.81,3.81; 6 1.27,3.81; 7 -1.27,3.81; 8 -3.81,3.81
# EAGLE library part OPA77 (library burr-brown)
Clamping Amplifier

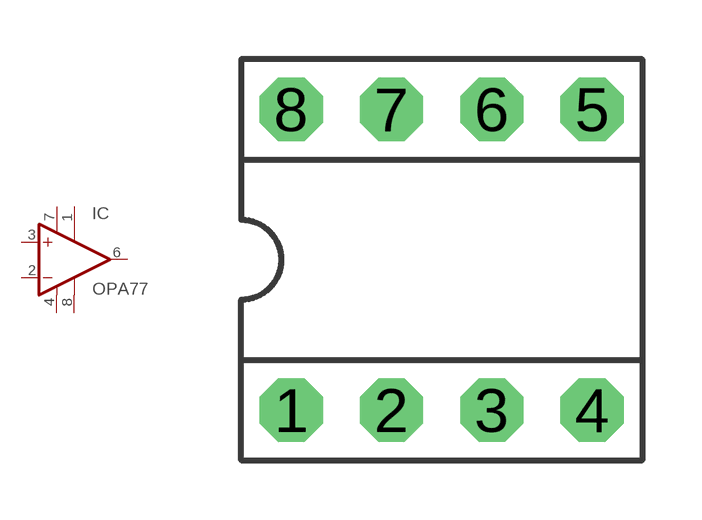
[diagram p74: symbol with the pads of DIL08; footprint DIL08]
Designator prefix IC

## OPA77P (OC_FARNELL: unknown; OC_NEWARK: unknown)  [DIL08]
1  TRIM1  pas
2  -IN  in
3  +IN  in
4  V-  pwr
6  OUT  out
7  V+  pwr
8  TRIM2  pas

## Footprint DIL08 (pad centres in mm)
Dual In Line
drill 0.813 pad 1.6 octagon: 1 -3.81,-3.81; 2 -1.27,-3.81; 3 1.27,-3.81; 4 3.81,-3.81; 5 3.81,3.81; 6 1.27,3.81; 7 -1.27,3.81; 8 -3.81,3.81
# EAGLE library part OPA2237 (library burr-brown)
Single-Supply Operational Amplifiers MicroAmplifier(TM) Series; Product Folder:OPA2237

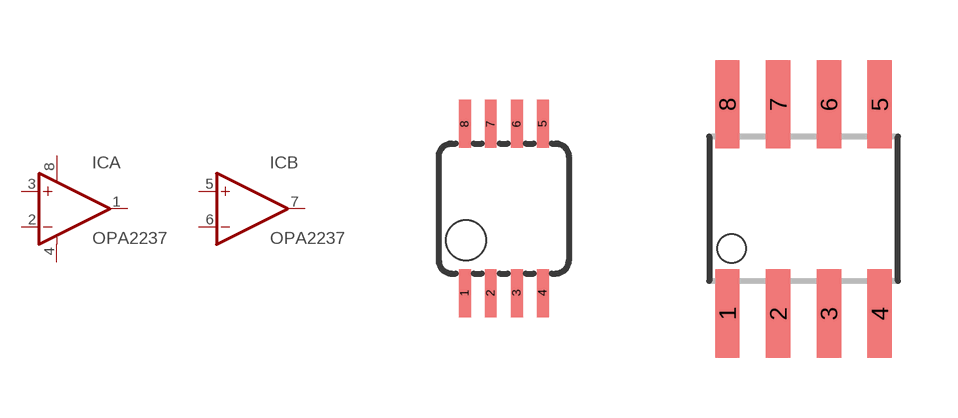
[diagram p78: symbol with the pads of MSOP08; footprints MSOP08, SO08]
Designator prefix IC; gates A=OP-AMP+- B=OP-AMP

## OPA2237E (MF: TEXAS INSTRUMENTS; MPN: OPA2237EA/250; OC_FARNELL: 1470365; OC_NEWARK: 35C1853)  [MSOP08]
1  A:OUT  out
2  A:-IN  in
3  A:+IN  in
4  A:V-  pwr
5  B:+IN  in
6  B:-IN  in
7  B:OUT  out
8  A:V+  pwr

## OPA2237U (MF: TEXAS INSTRUMENTS; MPN: OPA2237UA; OC_FARNELL: 1388075; OC_NEWARK: 80K6018)  [SO08]
Pads as for MSOP08

## Footprint MSOP08 (pad centres in mm)
Mini Small Outline Package
smd 0.3 x 1.2: 1 -0.976,-2.113; 2 -0.326,-2.113; 3 0.324,-2.113; 4 0.974,-2.113; 5 0.974,2.112; 6 0.324,2.112; 7 -0.326,2.112; 8 -0.976,2.112

## Footprint SO08 (pad centres in mm)
Small Outline Package
smd 0.61 x 2.21: 1 -1.905,-2.616; 2 -0.635,-2.616; 3 0.635,-2.616; 4 1.905,-2.616; 5 1.905,2.616; 6 0.635,2.616; 7 -0.635,2.616; 8 -1.905,2.616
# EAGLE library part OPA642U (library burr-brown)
Operational Amplifier

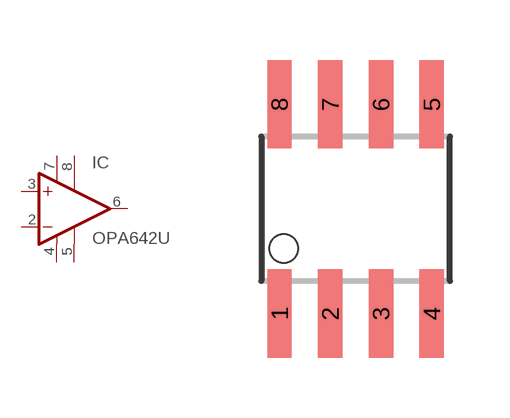
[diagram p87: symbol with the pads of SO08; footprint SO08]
Designator prefix IC

## OPA642U (MPN: AD9631ARZ; OC_FARNELL: 1319480; OC_NEWARK: 19M8943)  [SO08]
2  -IN  in
3  +IN  in
4  -VS1  pwr
5  -VS2  pwr
6  OUT  out
7  +VS1  pwr
8  +VS2  pwr

## Footprint SO08 (pad centres in mm)
Small Outline Package
smd 0.61 x 2.21: 1 -1.905,-2.616; 2 -0.635,-2.616; 3 0.635,-2.616; 4 1.905,-2.616; 5 1.905,2.616; 6 0.635,2.616; 7 -0.635,2.616; 8 -1.905,2.616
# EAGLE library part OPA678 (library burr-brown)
Operational Amplifier Wideband, Switched-Input

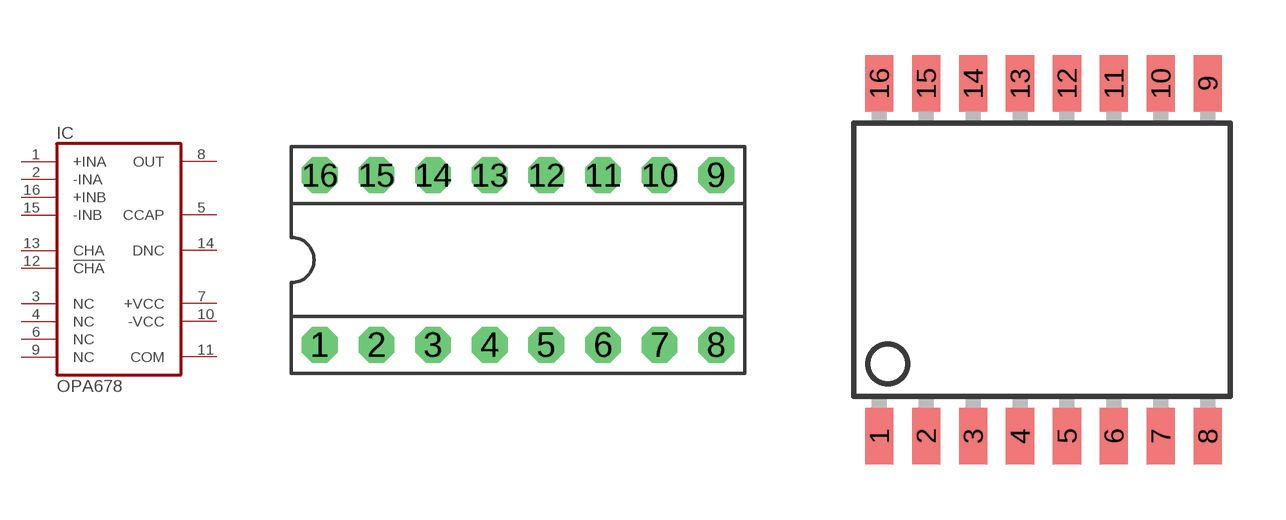
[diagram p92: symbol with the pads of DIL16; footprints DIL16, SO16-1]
Designator prefix IC

## OPA678P (OC_FARNELL: unknown; OC_NEWARK: unknown)  [DIL16]
1  +INA  in
2  -INA  in
3  NC  nc
4  NC  nc
5  CCAP  pas
6  NC  nc
7  +VCC  pwr
8  OUT  out
9  NC  nc
10  -VCC  pwr
11  COM  pwr
12  !CHA  in
13  CHA  in
14  DNC  pas
15  -INB  in
16  +INB  in

## OPA678U (OC_FARNELL: unknown; OC_NEWARK: unknown)  [SO16-1]
Pads as for DIL16

## Footprint DIL16 (pad centres in mm)
Dual In Line
drill 0.813 pad 1.6 octagon: 1 -8.89,-3.81; 2 -6.35,-3.81; 3 -3.81,-3.81; 4 -1.27,-3.81; 5 1.27,-3.81; 6 3.81,-3.81; 7 6.35,-3.81; 8 8.89,-3.81; 9 8.89,3.81; 10 6.35,3.81; 11 3.81,3.81; 12 1.27,3.81; 13 -1.27,3.81; 14 -3.81,3.81; 15 -6.35,3.81; 16 -8.89,3.81

## Footprint SO16-1 (pad centres in mm)
Small Outline Package
smd 0.762 x 1.524: 1 -4.445,-4.775; 2 -3.175,-4.775; 3 -1.905,-4.775; 4 -0.635,-4.775; 5 0.635,-4.775; 6 1.905,-4.775; 7 3.175,-4.775; 8 4.445,-4.775; 9 4.445,4.775; 10 3.175,4.775; 11 1.905,4.775; 12 0.635,4.775; 13 -0.635,4.775; 14 -1.905,4.775; 15 -3.175,4.775; 16 -4.445,4.775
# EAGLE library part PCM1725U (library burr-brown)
SoundPlus(TM) Stereo Audio DAConverter 16 Bits, 96kHz Sampling

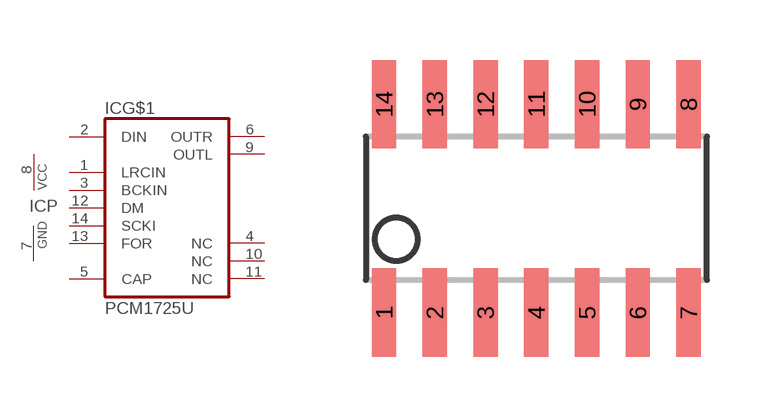
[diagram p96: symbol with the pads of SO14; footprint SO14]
Designator prefix IC; gates G$1=PCM1725 P=PWRN

## PCM1725U (MF: TEXAS INSTRUMENTS; MPN: PCM1725U; OC_FARNELL: unknown; OC_NEWARK: 34K8597)  [SO14]
1  G$1:LRCIN  in
2  G$1:DIN  in
3  G$1:BCKIN  in
4  G$1:NC  nc
5  G$1:CAP  pas
6  G$1:OUTR  out
7  P:GND  pwr
8  P:VCC  pwr
9  G$1:OUTL  out
10  G$1:NC  nc
11  G$1:NC  nc
12  G$1:DM  in
13  G$1:FOR  in
14  G$1:SCKI  in

## Footprint SO14 (pad centres in mm)
Small Outline Package
smd 0.61 x 2.21: 1 -3.81,-2.603; 2 -2.54,-2.603; 3 -1.27,-2.603; 4 0,-2.603; 5 1.27,-2.603; 6 2.54,-2.603; 7 3.81,-2.603; 8 3.81,2.603; 9 2.54,2.603; 10 1.27,2.603; 11 0,2.603; 12 -1.27,2.603; 13 -2.54,2.603; 14 -3.81,2.603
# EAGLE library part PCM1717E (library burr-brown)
SoundPlus(TM) Stereo Audio DAC

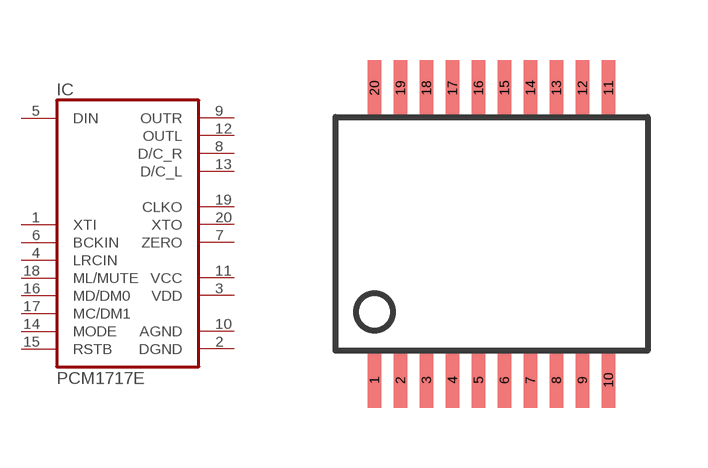
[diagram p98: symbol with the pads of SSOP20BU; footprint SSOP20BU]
Designator prefix IC

## PCM1717E (MF: TEXAS INSTRUMENTS; MPN: PCM1717E; OC_FARNELL: unknown; OC_NEWARK: 34K8595)  [SSOP20BU]
1  XTI  in
2  DGND  pwr
3  VDD  pwr
4  LRCIN  in
5  DIN  in
6  BCKIN  in
7  ZERO  out
8  D/C_R  out
9  OUTR  out
10  AGND  pwr
11  VCC  pwr
12  OUTL  out
13  D/C_L  out
14  MODE  in
15  RSTB  in
16  MD/DM0  in
17  MC/DM1  in
18  ML/MUTE  in
19  CLKO  out
20  XTO  out

## Footprint SSOP20BU (pad centres in mm)
Small Shrink Outline Package
smd 0.348 x 1.397: 1 -2.925,-3.656; 2 -2.275,-3.656; 3 -1.625,-3.656; 4 -0.975,-3.656; 5 -0.325,-3.656; 6 0.325,-3.656; 7 0.975,-3.656; 8 1.625,-3.656; 9 2.275,-3.656; 10 2.925,-3.656; 11 2.925,3.656; 12 2.275,3.656; 13 1.625,3.656; 14 0.975,3.656; 15 0.325,3.656; 16 -0.325,3.656; 17 -0.975,3.656; 18 -1.625,3.656; 19 -2.275,3.656; 20 -2.925,3.656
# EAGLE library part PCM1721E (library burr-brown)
SoundPlus Stereo Audio DAC MPEG2/AC-3 Compatible

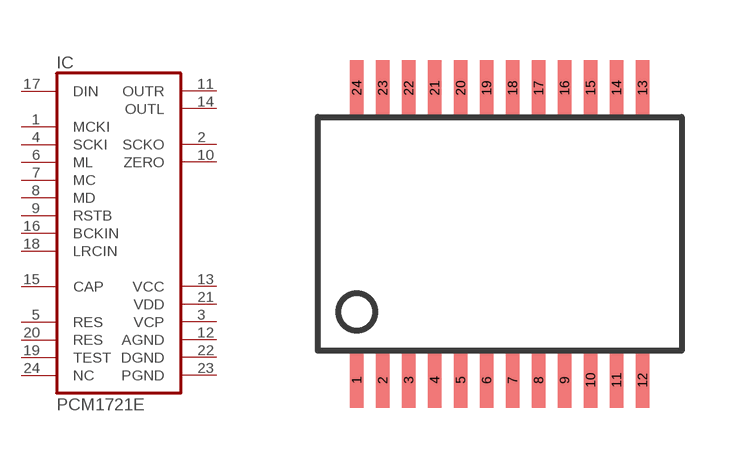
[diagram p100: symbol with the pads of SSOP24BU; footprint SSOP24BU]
Designator prefix IC

## PCM1721E (OC_FARNELL: unknown; OC_NEWARK: unknown)  [SSOP24BU]
1  MCKI  in
2  SCKO  out
3  VCP  pwr
4  SCKI  in
5  RES  pas
6  ML  in
7  MC  in
8  MD  in
9  RSTB  in
10  ZERO  out
11  OUTR  out
12  AGND  pwr
13  VCC  pwr
14  OUTL  out
15  CAP  pas
16  BCKIN  in
17  DIN  in
18  LRCIN  in
19  TEST  pas
20  RES  pas
21  VDD  pwr
22  DGND  pwr
23  PGND  pwr
24  NC  nc

## Footprint SSOP24BU (pad centres in mm)
Small Shrink Outline Package
smd 0.348 x 1.397: 1 -3.575,-3.656; 2 -2.925,-3.656; 3 -2.275,-3.656; 4 -1.625,-3.656; 5 -0.975,-3.656; 6 -0.325,-3.656; 7 0.325,-3.656; 8 0.975,-3.656; 9 1.625,-3.656; 10 2.275,-3.656; 11 2.925,-3.656; 12 3.575,-3.656; 13 3.575,3.656; 14 2.925,3.656; 15 2.275,3.656; 16 1.625,3.656; 17 0.975,3.656; 18 0.325,3.656; 19 -0.325,3.656; 20 -0.975,3.656; 21 -1.625,3.656; 22 -2.275,3.656; 23 -2.925,3.656; 24 -3.575,3.656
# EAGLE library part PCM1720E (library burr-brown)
SoundPlus(TM) Stereo Audio DAC MPEG2/AC-3 Compatible

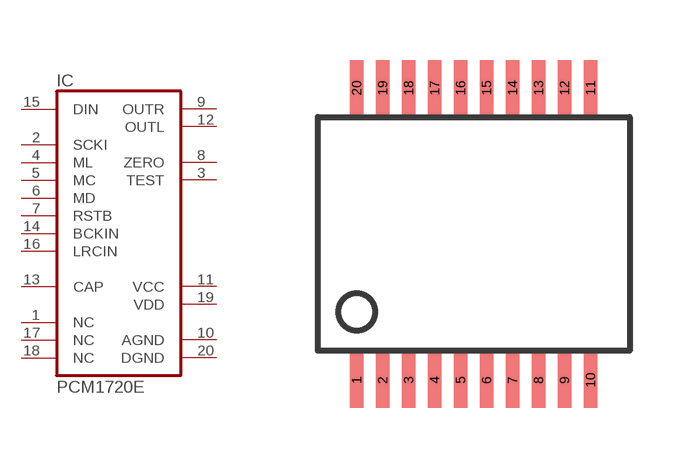
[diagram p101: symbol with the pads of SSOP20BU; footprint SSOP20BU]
Designator prefix IC

## PCM1720E (MPN: PCM1720E/2KG4; OC_FARNELL: unknown; OC_NEWARK: 66K4045)  [SSOP20BU]
1  NC  nc
2  SCKI  in
3  TEST  out
4  ML  in
5  MC  in
6  MD  in
7  RSTB  in
8  ZERO  out
9  OUTR  out
10  AGND  pwr
11  VCC  pwr
12  OUTL  out
13  CAP  pas
14  BCKIN  in
15  DIN  in
16  LRCIN  in
17  NC  nc
18  NC  nc
19  VDD  pwr
20  DGND  pwr

## Footprint SSOP20BU (pad centres in mm)
Small Shrink Outline Package
smd 0.348 x 1.397: 1 -2.925,-3.656; 2 -2.275,-3.656; 3 -1.625,-3.656; 4 -0.975,-3.656; 5 -0.325,-3.656; 6 0.325,-3.656; 7 0.975,-3.656; 8 1.625,-3.656; 9 2.275,-3.656; 10 2.925,-3.656; 11 2.925,3.656; 12 2.275,3.656; 13 1.625,3.656; 14 0.975,3.656; 15 0.325,3.656; 16 -0.325,3.656; 17 -0.975,3.656; 18 -1.625,3.656; 19 -2.275,3.656; 20 -2.925,3.656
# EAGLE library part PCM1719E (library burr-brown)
SoundPlus(TM) Stereo Audio DAC

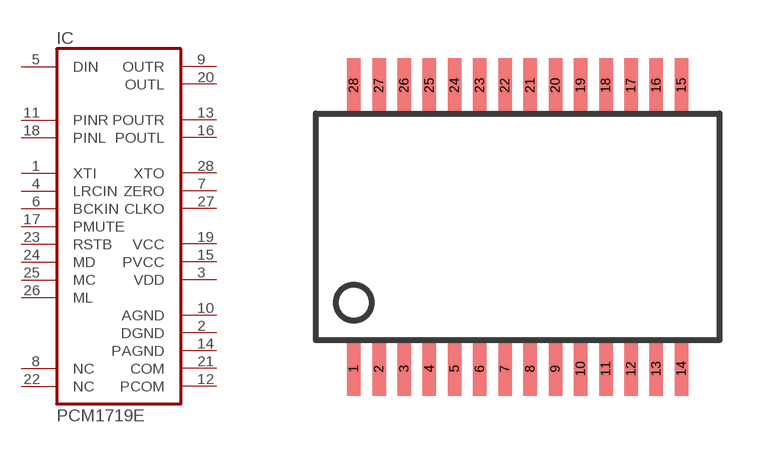
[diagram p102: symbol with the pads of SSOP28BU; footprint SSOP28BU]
Designator prefix IC

## PCM1719E (MPN: PCM1719E/2KG4; OC_FARNELL: unknown; OC_NEWARK: 67K8259)  [SSOP28BU]
1  XTI  in
2  DGND  pwr
3  VDD  pwr
4  LRCIN  in
5  DIN  in
6  BCKIN  in
7  ZERO  out
8  NC  nc
9  OUTR  out
10  AGND  pwr
11  PINR  in
12  PCOM  pwr
13  POUTR  out
14  PAGND  pwr
15  PVCC  pwr
16  POUTL  out
17  PMUTE  in
18  PINL  in
19  VCC  pwr
20  OUTL  out
21  COM  pwr
22  NC  nc
23  RSTB  in
24  MD  in
25  MC  in
26  ML  in
27  CLKO  out
28  XTO  out

## Footprint SSOP28BU (pad centres in mm)
Small Shrink Outline Package
smd 0.348 x 1.397: 1 -4.225,-3.656; 2 -3.575,-3.656; 3 -2.925,-3.656; 4 -2.275,-3.656; 5 -1.625,-3.656; 6 -0.975,-3.656; 7 -0.325,-3.656; 8 0.325,-3.656; 9 0.975,-3.656; 10 1.625,-3.656; 11 2.275,-3.656; 12 2.925,-3.656; 13 3.575,-3.656; 14 4.225,-3.656; 15 4.225,3.656; 16 3.575,3.656; 17 2.925,3.656; 18 2.275,3.656; 19 1.625,3.656; 20 0.975,3.656; 21 0.325,3.656; 22 -0.325,3.656; 23 -0.975,3.656; 24 -1.625,3.656; 25 -2.275,3.656; 26 -2.925,3.656; 27 -3.575,3.656; 28 -4.225,3.656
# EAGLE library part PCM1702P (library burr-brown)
BiCMOS Advanced Sign Magnitude 20-Bit DAC

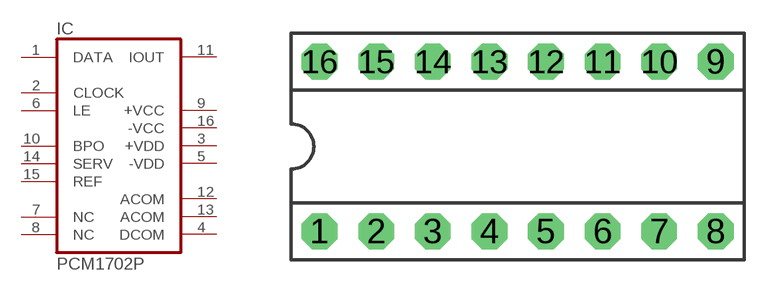
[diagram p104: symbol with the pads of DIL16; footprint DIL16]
Designator prefix IC

## PCM1702P (MF: TEXAS INSTRUMENT CONNECTORS; MPN: PCM1702P-J; OC_FARNELL: 1509912; OC_NEWARK: 75C5298)  [DIL16]
1  DATA  in
2  CLOCK  in
3  +VDD  pwr
4  DCOM  pwr
5  -VDD  pwr
6  LE  in
7  NC  nc
8  NC  nc
9  +VCC  pwr
10  BPO  pas
11  IOUT  out
12  ACOM  pwr
13  ACOM  pwr
14  SERV  pas
15  REF  pas
16  -VCC  pwr

## Footprint DIL16 (pad centres in mm)
Dual In Line
drill 0.813 pad 1.6 octagon: 1 -8.89,-3.81; 2 -6.35,-3.81; 3 -3.81,-3.81; 4 -1.27,-3.81; 5 1.27,-3.81; 6 3.81,-3.81; 7 6.35,-3.81; 8 8.89,-3.81; 9 8.89,3.81; 10 6.35,3.81; 11 3.81,3.81; 12 1.27,3.81; 13 -1.27,3.81; 14 -3.81,3.81; 15 -6.35,3.81; 16 -8.89,3.81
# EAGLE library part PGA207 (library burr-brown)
High-Speed Programmable Gain Instrumentation Amplifier

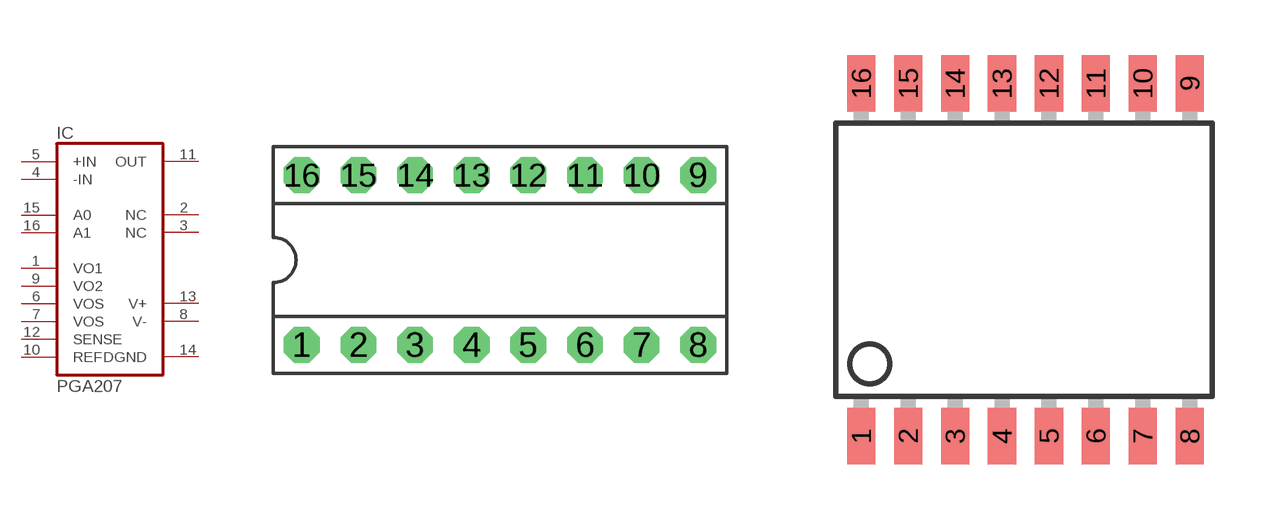
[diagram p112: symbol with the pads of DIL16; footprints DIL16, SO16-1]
Designator prefix IC

## PGA207P (OC_FARNELL: unknown; OC_NEWARK: unknown)  [DIL16]
1  VO1  pas
2  NC  nc
3  NC  nc
4  -IN  in
5  +IN  in
6  VOS  pas
7  VOS  pas
8  V-  pwr
9  VO2  pas
10  REF  pas
11  OUT  out
12  SENSE  pas
13  V+  pwr
14  DGND  pwr
15  A0  in
16  A1  in

## PGA207U (MF: TEXAS INSTRUMENTS; MPN: PGA207UA; OC_FARNELL: 1212338; OC_NEWARK: 75C5427)  [SO16-1]
Pads as for DIL16

## Footprint DIL16 (pad centres in mm)
Dual In Line
drill 0.813 pad 1.6 octagon: 1 -8.89,-3.81; 2 -6.35,-3.81; 3 -3.81,-3.81; 4 -1.27,-3.81; 5 1.27,-3.81; 6 3.81,-3.81; 7 6.35,-3.81; 8 8.89,-3.81; 9 8.89,3.81; 10 6.35,3.81; 11 3.81,3.81; 12 1.27,3.81; 13 -1.27,3.81; 14 -3.81,3.81; 15 -6.35,3.81; 16 -8.89,3.81

## Footprint SO16-1 (pad centres in mm)
Small Outline Package
smd 0.762 x 1.524: 1 -4.445,-4.775; 2 -3.175,-4.775; 3 -1.905,-4.775; 4 -0.635,-4.775; 5 0.635,-4.775; 6 1.905,-4.775; 7 3.175,-4.775; 8 4.445,-4.775; 9 4.445,4.775; 10 3.175,4.775; 11 1.905,4.775; 12 0.635,4.775; 13 -0.635,4.775; 14 -1.905,4.775; 15 -3.175,4.775; 16 -4.445,4.775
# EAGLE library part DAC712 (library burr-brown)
16-Bit DAC with 16-Bit Bus Interface

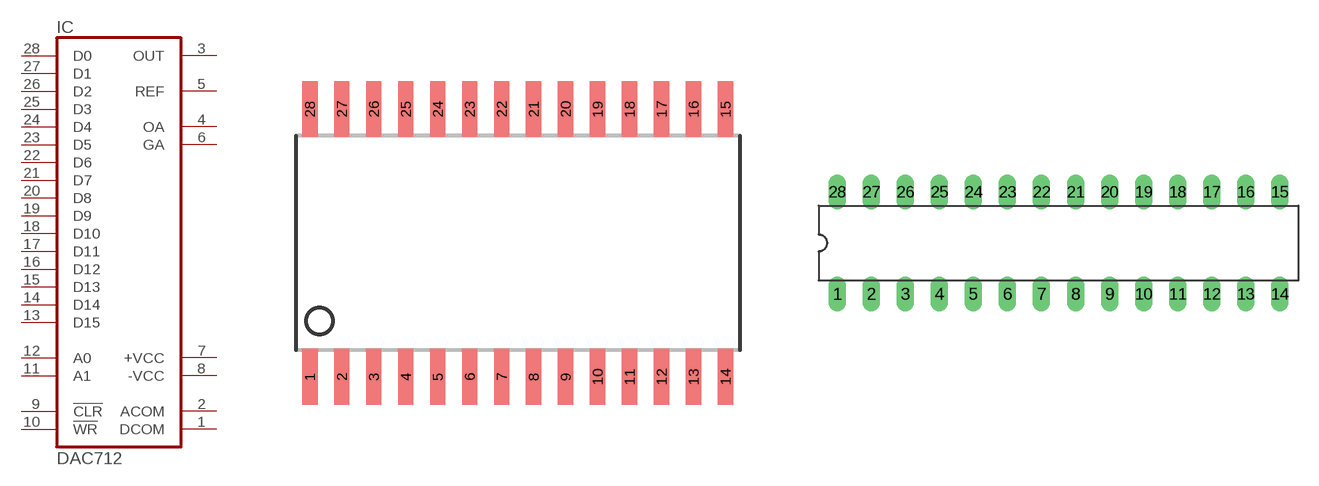
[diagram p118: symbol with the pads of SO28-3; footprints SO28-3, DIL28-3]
Designator prefix IC

## DAC712U (MF: TEXAS INSTRUMENTS; MPN: DAC712U; OC_FARNELL: 1097510; OC_NEWARK: 74C9132)  [SO28-3]
1  DCOM  pwr
2  ACOM  pwr
3  OUT  out
4  OA  pas
5  REF  out
6  GA  pas
7  +VCC  pwr
8  -VCC  pwr
9  !CLR  in
10  !WR  in
11  A1  in
12  A0  in
13  D15  in
14  D14  in
15  D13  in
16  D12  in
17  D11  in
18  D10  in
19  D9  in
20  D8  in
21  D7  in
22  D6  in
23  D5  in
24  D4  in
25  D3  in
26  D2  in
27  D1  in
28  D0  in

## DAC712P (MF: TEXAS INSTRUMENT CONNECTORS; MPN: DAC712P; OC_FARNELL: unknown; OC_NEWARK: 04M4506)  [DIL28-3]
Pads as for SO28-3

## Footprint SO28-3 (pad centres in mm)
Small Outline Package
smd 0.61 x 2.21: 1 -8.255,-5.315; 2 -6.985,-5.315; 3 -5.715,-5.315; 4 -4.445,-5.315; 5 -3.175,-5.315; 6 -1.905,-5.315; 7 -0.635,-5.315; 8 0.635,-5.315; 9 1.905,-5.315; 10 3.175,-5.315; 11 4.445,-5.315; 12 5.715,-5.315; 13 6.985,-5.315; 14 8.255,-5.315; 15 8.255,5.315; 16 6.985,5.315; 17 5.715,5.315; 18 4.445,5.315; 19 3.175,5.315; 20 1.905,5.315; 21 0.635,5.315; 22 -0.635,5.315; 23 -1.905,5.315; 24 -3.175,5.315; 25 -4.445,5.315; 26 -5.715,5.315; 27 -6.985,5.315; 28 -8.255,5.315

## Footprint DIL28-3 (pad centres in mm)
Dual In Line 0.3 inch
drill 0.813 long: 1 -16.51,-3.81; 2 -13.97,-3.81; 3 -11.43,-3.81; 4 -8.89,-3.81; 5 -6.35,-3.81; 6 -3.81,-3.81; 7 -1.27,-3.81; 8 1.27,-3.81; 9 3.81,-3.81; 10 6.35,-3.81; 11 8.89,-3.81; 12 11.43,-3.81; 13 13.97,-3.81; 14 16.51,-3.81; 15 16.51,3.81; 16 13.97,3.81; 17 11.43,3.81; 18 8.89,3.81; 19 6.35,3.81; 20 3.81,3.81; 21 1.27,3.81; 22 -1.27,3.81; 23 -3.81,3.81; 24 -6.35,3.81; 25 -8.89,3.81; 26 -11.43,3.81; 27 -13.97,3.81; 28 -16.51,3.81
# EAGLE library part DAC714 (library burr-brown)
16-Bit DAC with Serial Data Interface

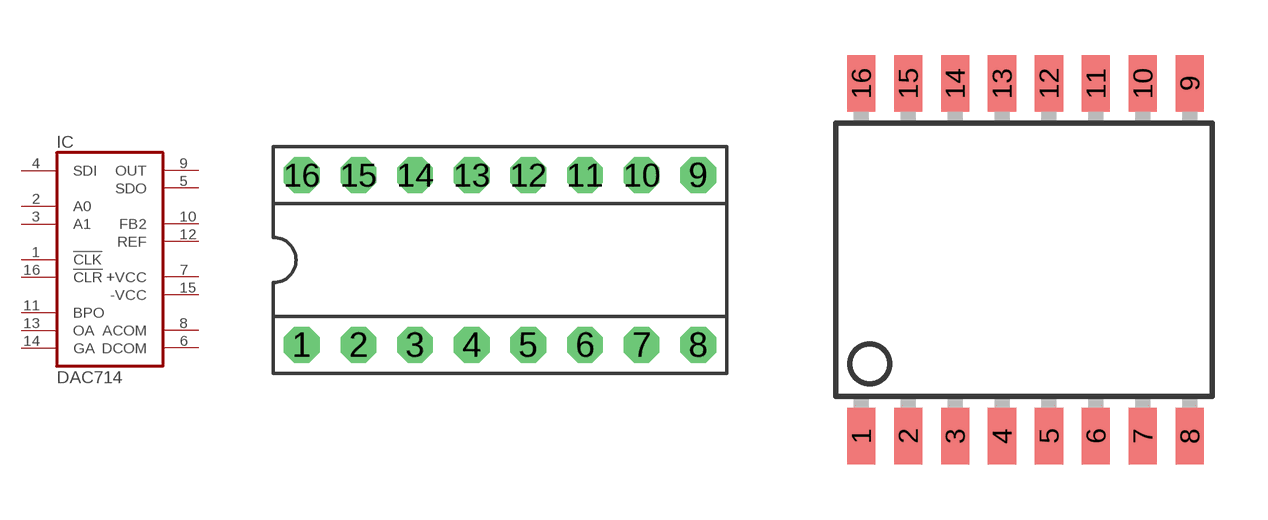
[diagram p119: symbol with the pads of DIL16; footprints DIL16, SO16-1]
Designator prefix IC

## DAC714P (MF: TEXAS INSTRUMENT CONNECTORS; MPN: DAC714P; OC_FARNELL: 1254318; OC_NEWARK: 78K7952)  [DIL16]
1  !CLK  in
2  A0  in
3  A1  in
4  SDI  in
5  SDO  out
6  DCOM  pwr
7  +VCC  pwr
8  ACOM  pwr
9  OUT  out
10  FB2  out
11  BPO  pas
12  REF  out
13  OA  pas
14  GA  pas
15  -VCC  pwr
16  !CLR  in

## DAC714U (MF: TEXAS INSTRUMENTS; MPN: DAC714U; OC_FARNELL: 1214385; OC_NEWARK: 17M6575)  [SO16-1]
Pads as for DIL16

## Footprint DIL16 (pad centres in mm)
Dual In Line
drill 0.813 pad 1.6 octagon: 1 -8.89,-3.81; 2 -6.35,-3.81; 3 -3.81,-3.81; 4 -1.27,-3.81; 5 1.27,-3.81; 6 3.81,-3.81; 7 6.35,-3.81; 8 8.89,-3.81; 9 8.89,3.81; 10 6.35,3.81; 11 3.81,3.81; 12 1.27,3.81; 13 -1.27,3.81; 14 -3.81,3.81; 15 -6.35,3.81; 16 -8.89,3.81

## Footprint SO16-1 (pad centres in mm)
Small Outline Package
smd 0.762 x 1.524: 1 -4.445,-4.775; 2 -3.175,-4.775; 3 -1.905,-4.775; 4 -0.635,-4.775; 5 0.635,-4.775; 6 1.905,-4.775; 7 3.175,-4.775; 8 4.445,-4.775; 9 4.445,4.775; 10 3.175,4.775; 11 1.905,4.775; 12 0.635,4.775; 13 -0.635,4.775; 14 -1.905,4.775; 15 -3.175,4.775; 16 -4.445,4.775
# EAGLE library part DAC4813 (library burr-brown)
Quad 12-Bit DAC 12-bit port Interface

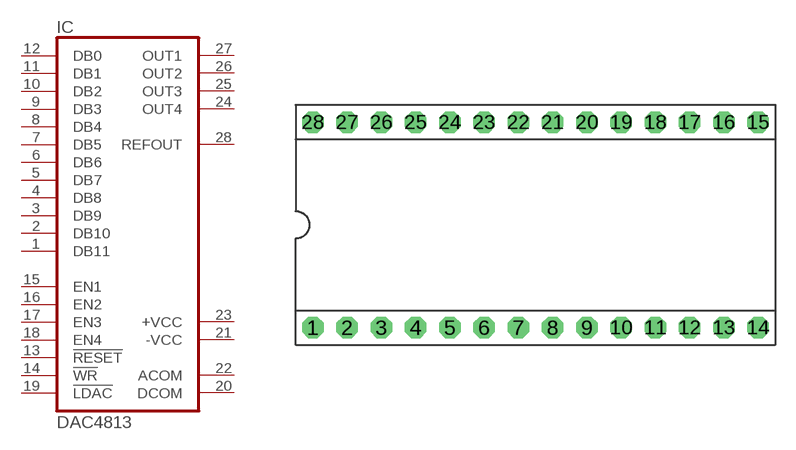
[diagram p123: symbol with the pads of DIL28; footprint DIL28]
Designator prefix IC

## DAC4813P (OC_FARNELL: unknown; OC_NEWARK: unknown)  [DIL28]
1  DB11  in
2  DB10  in
3  DB9  in
4  DB8  in
5  DB7  in
6  DB6  in
7  DB5  in
8  DB4  in
9  DB3  in
10  DB2  in
11  DB1  in
12  DB0  in
13  !RESET  in
14  !WR  in
15  EN1  in
16  EN2  in
17  EN3  in
18  EN4  in
19  !LDAC  in
20  DCOM  pwr
21  -VCC  pwr
22  ACOM  pwr
23  +VCC  pwr
24  OUT4  out
25  OUT3  out
26  OUT2  out
27  OUT1  out
28  REFOUT  out

## Footprint DIL28 (pad centres in mm)
Dual In Line
drill 0.813 pad 1.6 octagon: 1 -16.51,-7.62; 2 -13.97,-7.62; 3 -11.43,-7.62; 4 -8.89,-7.62; 5 -6.35,-7.62; 6 -3.81,-7.62; 7 -1.27,-7.62; 8 1.27,-7.62; 9 3.81,-7.62; 10 6.35,-7.62; 11 8.89,-7.62; 12 11.43,-7.62; 13 13.97,-7.62; 14 16.51,-7.62; 15 16.51,7.62; 16 13.97,7.62; 17 11.43,7.62; 18 8.89,7.62; 19 6.35,7.62; 20 3.81,7.62; 21 1.27,7.62; 22 -1.27,7.62; 23 -3.81,7.62; 24 -6.35,7.62; 25 -8.89,7.62; 26 -11.43,7.62; 27 -13.97,7.62; 28 -16.51,7.62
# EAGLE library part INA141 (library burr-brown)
Instrumentation Amplifier</b Precision, Low Power, G = 10, 100

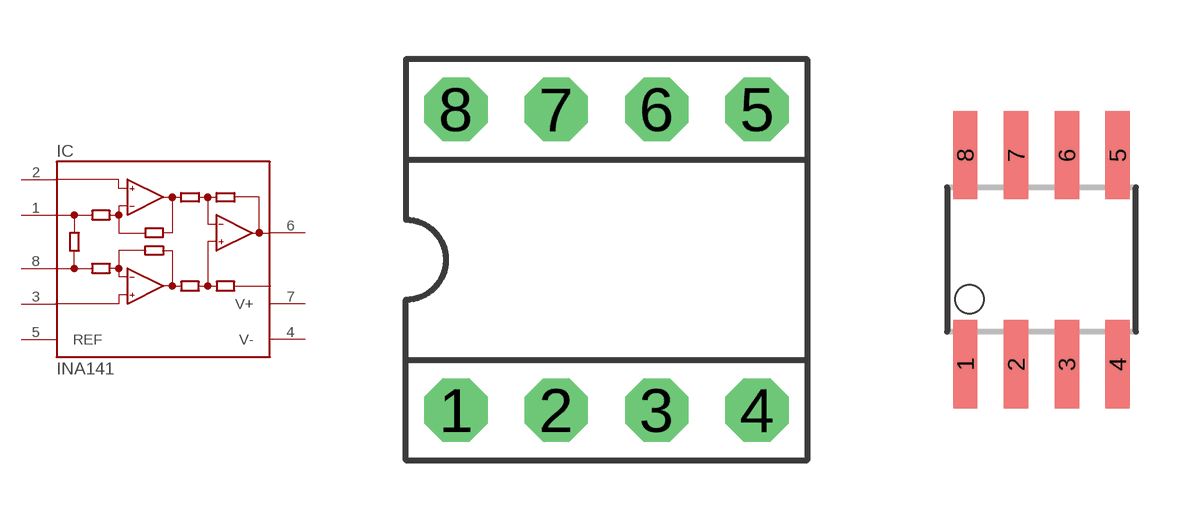
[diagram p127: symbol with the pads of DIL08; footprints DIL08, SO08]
Designator prefix IC

## INA141P (OC_FARNELL: unknown; OC_NEWARK: unknown)  [DIL08]
1  J  pas
2  -IN  in
3  +IN  in
4  V-  pwr
5  REF  pas
6  OUT  out
7  V+  pwr
8  J  pas

## INA141U (MF: TEXAS INSTRUMENTS; MPN: INA141U; OC_FARNELL: 1212419; OC_NEWARK: 80K5907)  [SO08]
Pads as for DIL08

## Footprint DIL08 (pad centres in mm)
Dual In Line
drill 0.813 pad 1.6 octagon: 1 -3.81,-3.81; 2 -1.27,-3.81; 3 1.27,-3.81; 4 3.81,-3.81; 5 3.81,3.81; 6 1.27,3.81; 7 -1.27,3.81; 8 -3.81,3.81

## Footprint SO08 (pad centres in mm)
Small Outline Package
smd 0.61 x 2.21: 1 -1.905,-2.616; 2 -0.635,-2.616; 3 0.635,-2.616; 4 1.905,-2.616; 5 1.905,2.616; 6 0.635,2.616; 7 -0.635,2.616; 8 -1.905,2.616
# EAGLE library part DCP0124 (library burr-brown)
DC/DC Converters Miniature 24V Input, 1W Isolated Unregulated

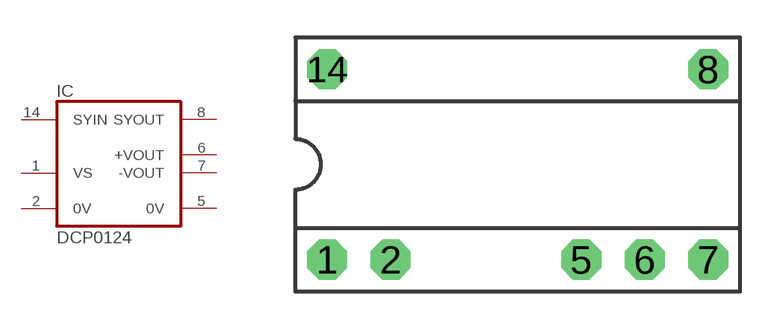
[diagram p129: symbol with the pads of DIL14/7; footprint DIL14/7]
Designator prefix IC

## DCP0124D (MF: TEXAS INSTRUMENTS; MPN: DCP012415DBP-U; OC_FARNELL: 1247063; OC_NEWARK: 76K4235)  [DIL14/7]
1  VS  pwr
2  0V  pwr
5  0V  pwr
6  +VOUT  pwr
7  -VOUT  nc
8  SYOUT  out
14  SYIN  in

## Footprint DIL14/7 (pad centres in mm)
Dual In Line
drill 0.813 pad 1.6 octagon: 1 -7.62,-3.81; 2 -5.08,-3.81; 5 2.54,-3.81; 6 5.08,-3.81; 7 7.62,-3.81; 8 7.62,3.81; 14 -7.62,3.81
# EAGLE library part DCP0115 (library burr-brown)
DC/DC Converters Miniature 15V Input, 1W Isolated Unregulated

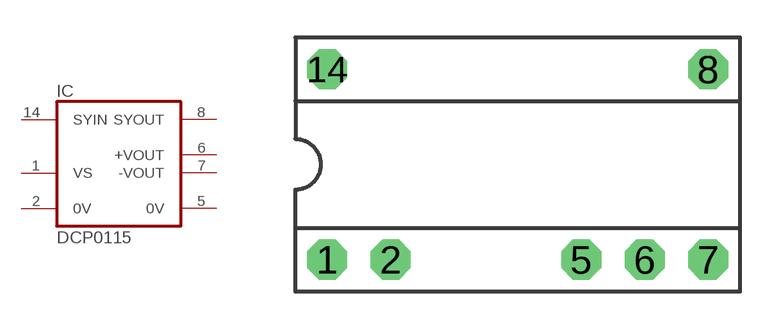
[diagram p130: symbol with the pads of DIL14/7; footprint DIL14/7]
Designator prefix IC

## DCP0115P (MF: TEXAS INSTRUMENT CONNECTORS; MPN: DCP011512DBP; OC_FARNELL: 1461019; OC_NEWARK: 74K3725)  [DIL14/7]
1  VS  pwr
2  0V  pwr
5  0V  pwr
6  +VOUT  pwr
7  -VOUT  nc
8  SYOUT  out
14  SYIN  in

## Footprint DIL14/7 (pad centres in mm)
Dual In Line
drill 0.813 pad 1.6 octagon: 1 -7.62,-3.81; 2 -5.08,-3.81; 5 2.54,-3.81; 6 5.08,-3.81; 7 7.62,-3.81; 8 7.62,3.81; 14 -7.62,3.81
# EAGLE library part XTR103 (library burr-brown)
4-20mA Current Transmitter with RTD Excitation And Linearization

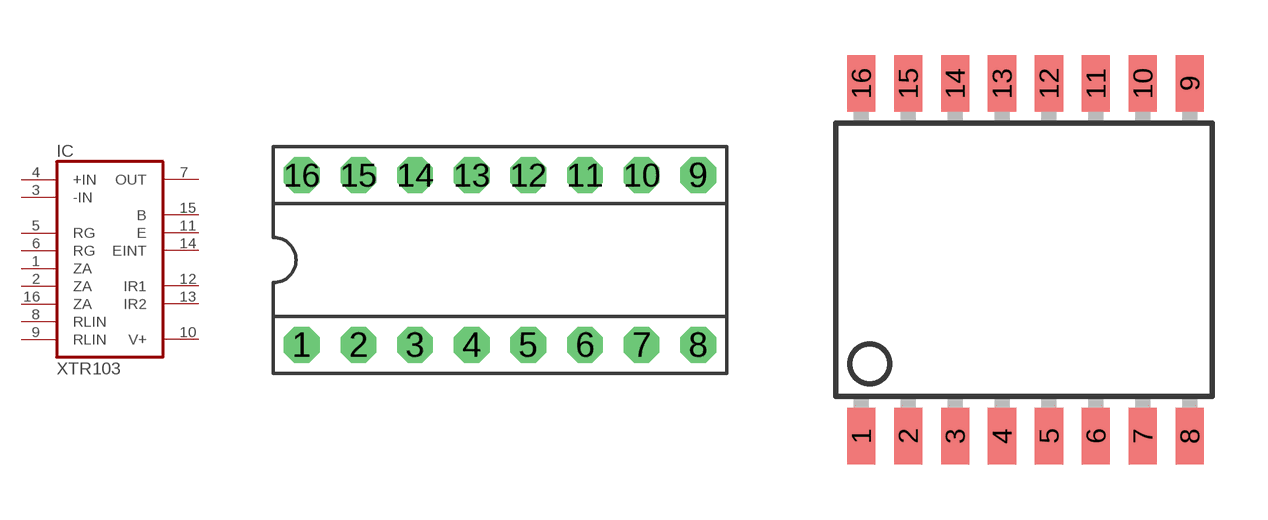
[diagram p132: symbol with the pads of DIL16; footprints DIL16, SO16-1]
Designator prefix IC

## XTR103P (OC_FARNELL: unknown; OC_NEWARK: unknown)  [DIL16]
1  ZA  pas
2  ZA  pas
3  -IN  in
4  +IN  in
5  RG  pas
6  RG  pas
7  OUT  out
8  RLIN  pas
9  RLIN  pas
10  V+  pwr
11  E  out
12  IR1  pas
13  IR2  pas
14  EINT  pas
15  B  out
16  ZA  pas

## XTR103U (OC_FARNELL: unknown; OC_NEWARK: unknown)  [SO16-1]
Pads as for DIL16

## Footprint DIL16 (pad centres in mm)
Dual In Line
drill 0.813 pad 1.6 octagon: 1 -8.89,-3.81; 2 -6.35,-3.81; 3 -3.81,-3.81; 4 -1.27,-3.81; 5 1.27,-3.81; 6 3.81,-3.81; 7 6.35,-3.81; 8 8.89,-3.81; 9 8.89,3.81; 10 6.35,3.81; 11 3.81,3.81; 12 1.27,3.81; 13 -1.27,3.81; 14 -3.81,3.81; 15 -6.35,3.81; 16 -8.89,3.81

## Footprint SO16-1 (pad centres in mm)
Small Outline Package
smd 0.762 x 1.524: 1 -4.445,-4.775; 2 -3.175,-4.775; 3 -1.905,-4.775; 4 -0.635,-4.775; 5 0.635,-4.775; 6 1.905,-4.775; 7 3.175,-4.775; 8 4.445,-4.775; 9 4.445,4.775; 10 3.175,4.775; 11 1.905,4.775; 12 0.635,4.775; 13 -0.635,4.775; 14 -1.905,4.775; 15 -3.175,4.775; 16 -4.445,4.775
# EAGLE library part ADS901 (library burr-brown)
10-Bit, 20 MSPS ADC SE/Diff Inputs Ext Reference and Adjustable Fullscale Range

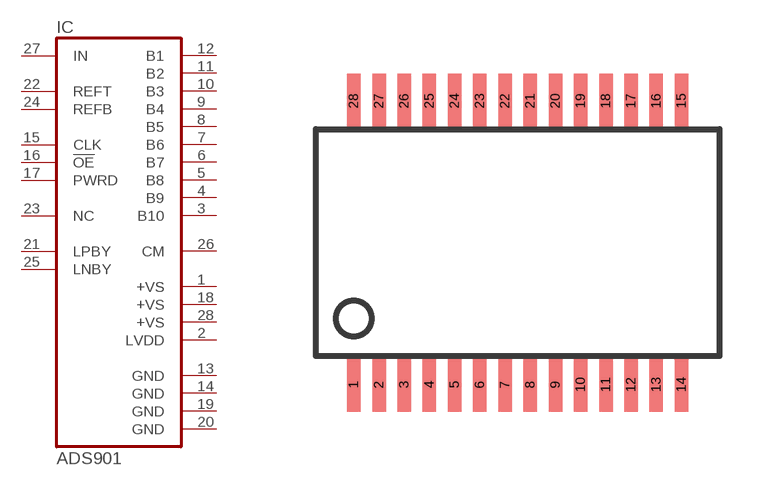
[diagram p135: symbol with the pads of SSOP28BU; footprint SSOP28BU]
Designator prefix IC

## ADS901E (MF: TEXAS INSTRUMENT CONNECTORS; MPN: ADS901E; OC_FARNELL: 1509526; OC_NEWARK: 35C1591)  [SSOP28BU]
1  +VS  pwr
2  LVDD  pwr
3  B10  out
4  B9  out
5  B8  out
6  B7  out
7  B6  out
8  B5  out
9  B4  out
10  B3  out
11  B2  out
12  B1  out
13  GND  pwr
14  GND  pwr
15  CLK  in
16  !OE  in
17  PWRD  in
18  +VS  pwr
19  GND  pwr
20  GND  pwr
21  LPBY  pas
22  REFT  in
23  NC  nc
24  REFB  in
25  LNBY  pas
26  CM  out
27  IN  in
28  +VS  pwr

## Footprint SSOP28BU (pad centres in mm)
Small Shrink Outline Package
smd 0.348 x 1.397: 1 -4.225,-3.656; 2 -3.575,-3.656; 3 -2.925,-3.656; 4 -2.275,-3.656; 5 -1.625,-3.656; 6 -0.975,-3.656; 7 -0.325,-3.656; 8 0.325,-3.656; 9 0.975,-3.656; 10 1.625,-3.656; 11 2.275,-3.656; 12 2.925,-3.656; 13 3.575,-3.656; 14 4.225,-3.656; 15 4.225,3.656; 16 3.575,3.656; 17 2.925,3.656; 18 2.275,3.656; 19 1.625,3.656; 20 0.975,3.656; 21 0.325,3.656; 22 -0.325,3.656; 23 -0.975,3.656; 24 -1.625,3.656; 25 -2.275,3.656; 26 -2.925,3.656; 27 -3.575,3.656; 28 -4.225,3.656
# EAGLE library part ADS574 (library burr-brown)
Sampling CMOS A/D Converter Microprocessor-Compatible

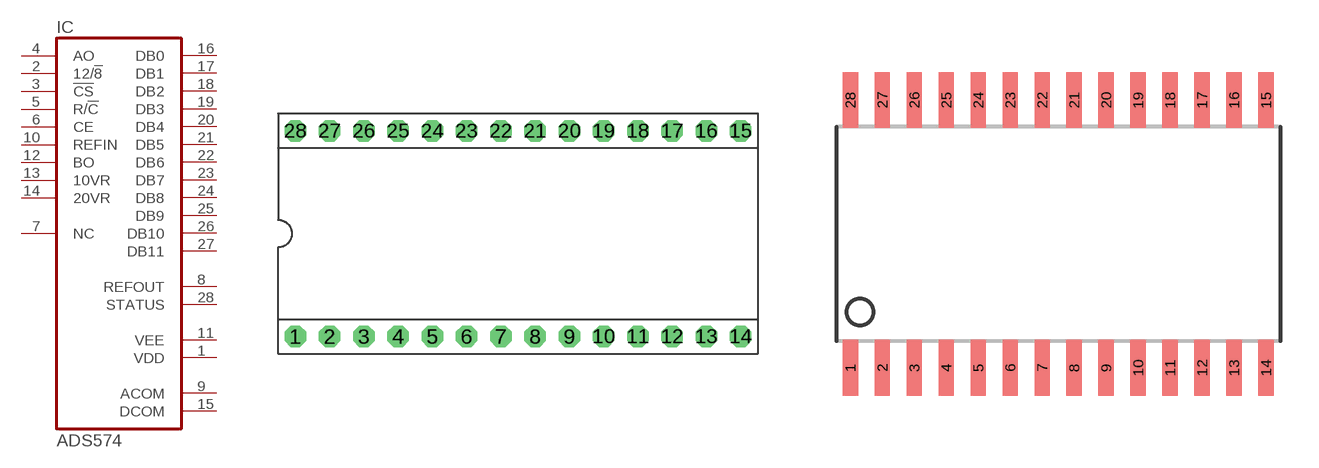
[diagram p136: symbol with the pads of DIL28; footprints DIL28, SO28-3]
Designator prefix IC

## ADS574P (MF: TEXAS INSTRUMENT CONNECTORS; MPN: ADS574JP; OC_FARNELL: 1311734; OC_NEWARK: 88K1031)  [DIL28]
1  VDD  pwr
2  12/!8  in
3  !CS  in
4  AO  in
5  R/!C  in
6  CE  in
7  NC  nc
8  REFOUT  out
9  ACOM  pwr
10  REFIN  in
11  VEE  pwr
12  BO  in
13  10VR  in
14  20VR  in
15  DCOM  pwr
16  DB0  out
17  DB1  out
18  DB2  out
19  DB3  out
20  DB4  out
21  DB5  out
22  DB6  out
23  DB7  out
24  DB8  out
25  DB9  out
26  DB10  out
27  DB11  out
28  STATUS  out

## ADS574U (OC_FARNELL: unknown; OC_NEWARK: unknown)  [SO28-3]
Pads as for DIL28

## ADS574JE (MPN: ADS574JE; OC_FARNELL: 1214401; OC_NEWARK: 01M6815)  [DIL28-3]
1  VDD  pwr
2  12/!8  in
3  !CS  in
4  AO  in
5  R/!C  in
6  CE  in
7  NC  nc
8  REFOUT  out
9  ACOM  pwr
10  REFIN  in
11  VEE  pwr
12  BO  in
13  10VR  in
14  20VR  in
15  DCOM  pwr
16  DB11  out
17  DB10  out
18  DB9  out
19  DB8  out
20  DB7  out
21  DB6  out
22  DB5  out
23  DB4  out
24  DB3  out
25  DB2  out
26  DB1  out
27  DB0  out
28  STATUS  out

## Footprint DIL28 (pad centres in mm)
Dual In Line
drill 0.813 pad 1.6 octagon: 1 -16.51,-7.62; 2 -13.97,-7.62; 3 -11.43,-7.62; 4 -8.89,-7.62; 5 -6.35,-7.62; 6 -3.81,-7.62; 7 -1.27,-7.62; 8 1.27,-7.62; 9 3.81,-7.62; 10 6.35,-7.62; 11 8.89,-7.62; 12 11.43,-7.62; 13 13.97,-7.62; 14 16.51,-7.62; 15 16.51,7.62; 16 13.97,7.62; 17 11.43,7.62; 18 8.89,7.62; 19 6.35,7.62; 20 3.81,7.62; 21 1.27,7.62; 22 -1.27,7.62; 23 -3.81,7.62; 24 -6.35,7.62; 25 -8.89,7.62; 26 -11.43,7.62; 27 -13.97,7.62; 28 -16.51,7.62

## Footprint SO28-3 (pad centres in mm)
Small Outline Package
smd 0.61 x 2.21: 1 -8.255,-5.315; 2 -6.985,-5.315; 3 -5.715,-5.315; 4 -4.445,-5.315; 5 -3.175,-5.315; 6 -1.905,-5.315; 7 -0.635,-5.315; 8 0.635,-5.315; 9 1.905,-5.315; 10 3.175,-5.315; 11 4.445,-5.315; 12 5.715,-5.315; 13 6.985,-5.315; 14 8.255,-5.315; 15 8.255,5.315; 16 6.985,5.315; 17 5.715,5.315; 18 4.445,5.315; 19 3.175,5.315; 20 1.905,5.315; 21 0.635,5.315; 22 -0.635,5.315; 23 -1.905,5.315; 24 -3.175,5.315; 25 -4.445,5.315; 26 -5.715,5.315; 27 -6.985,5.315; 28 -8.255,5.315

## Footprint DIL28-3 (pad centres in mm)
Dual In Line 0.3 inch
drill 0.813 long: 1 -16.51,-3.81; 2 -13.97,-3.81; 3 -11.43,-3.81; 4 -8.89,-3.81; 5 -6.35,-3.81; 6 -3.81,-3.81; 7 -1.27,-3.81; 8 1.27,-3.81; 9 3.81,-3.81; 10 6.35,-3.81; 11 8.89,-3.81; 12 11.43,-3.81; 13 13.97,-3.81; 14 16.51,-3.81; 15 16.51,3.81; 16 13.97,3.81; 17 11.43,3.81; 18 8.89,3.81; 19 6.35,3.81; 20 3.81,3.81; 21 1.27,3.81; 22 -1.27,3.81; 23 -3.81,3.81; 24 -6.35,3.81; 25 -8.89,3.81; 26 -11.43,3.81; 27 -13.97,3.81; 28 -16.51,3.81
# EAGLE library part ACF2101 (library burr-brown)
Dual Switched Integrator

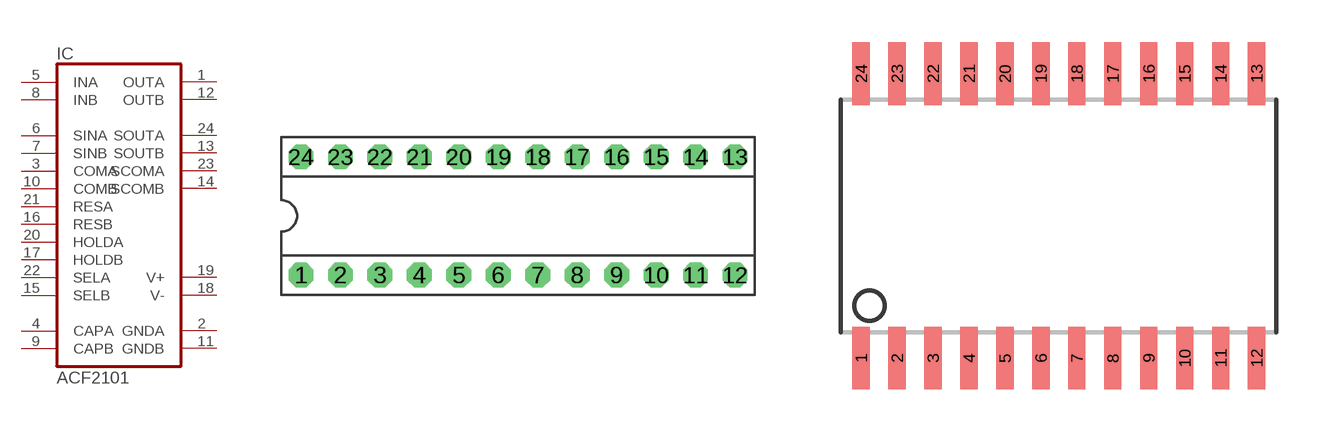
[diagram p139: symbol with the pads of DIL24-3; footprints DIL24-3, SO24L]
Designator prefix IC

## ACF2101P (OC_FARNELL: unknown; OC_NEWARK: unknown)  [DIL24-3]
1  OUTA  out
2  GNDA  pwr
3  COMA  in
4  CAPA  pas
5  INA  in
6  SINA  in
7  SINB  in
8  INB  in
9  CAPB  pas
10  COMB  in
11  GNDB  pwr
12  OUTB  out
13  SOUTB  out
14  SCOMB  out
15  SELB  in
16  RESB  in
17  HOLDB  in
18  V-  pwr
19  V+  pwr
20  HOLDA  in
21  RESA  in
22  SELA  in
23  SCOMA  out
24  SOUTA  out

## ACF2101U (MPN: ACF2101BU.; OC_FARNELL: 1206857; OC_NEWARK: 34R6526)  [SO24L]
1  SINB  in
2  INB  in
3  CAPB  pas
4  COMB  in
5  GNDB  pwr
6  OUTB  out
7  SOUTB  out
8  SCOMB  out
9  SELB  in
10  RESB  in
11  HOLDB  in
12  V-  pwr
13  V+  pwr
14  HOLDA  in
15  RESA  in
16  SELA  in
17  SCOMA  out
18  SOUTA  out
19  OUTA  out
20  GNDA  pwr
21  COMA  in
22  CAPA  pas
23  INA  in
24  SINA  in

## Footprint DIL24-3 (pad centres in mm)
Dual In Line 0.3 inch
drill 0.813 pad 1.6 octagon: 1 -13.97,-3.81; 2 -11.43,-3.81; 3 -8.89,-3.81; 4 -6.35,-3.81; 5 -3.81,-3.81; 6 -1.27,-3.81; 7 1.27,-3.81; 8 3.81,-3.81; 9 6.35,-3.81; 10 8.89,-3.81; 11 11.43,-3.81; 12 13.97,-3.81; 13 13.97,3.81; 14 11.43,3.81; 15 8.89,3.81; 16 6.35,3.81; 17 3.81,3.81; 18 1.27,3.81; 19 -1.27,3.81; 20 -3.81,3.81; 21 -6.35,3.81; 22 -8.89,3.81; 23 -11.43,3.81; 24 -13.97,3.81

## Footprint SO24L (pad centres in mm)
Small Outline Package, large
smd 0.61 x 2.21: 1 -6.985,-5.029; 2 -5.715,-5.029; 3 -4.445,-5.029; 4 -3.175,-5.029; 5 -1.905,-5.029; 6 -0.635,-5.029; 7 0.635,-5.029; 8 1.905,-5.029; 9 3.175,-5.029; 10 4.445,-5.029; 11 5.715,-5.029; 12 6.985,-5.029; 13 6.985,5.029; 14 5.715,5.029; 15 4.445,5.029; 16 3.175,5.029; 17 1.905,5.029; 18 0.635,5.029; 19 -0.635,5.029; 20 -1.905,5.029; 21 -3.175,5.029; 22 -4.445,5.029; 23 -5.715,5.029; 24 -6.985,5.029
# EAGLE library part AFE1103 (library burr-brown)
HDSL/MDSL Analog Front End

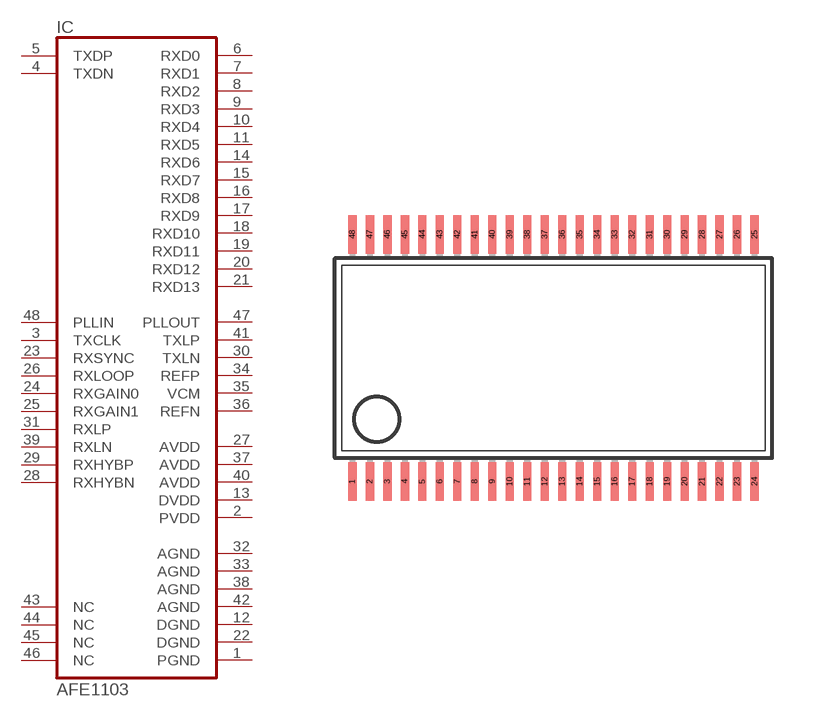
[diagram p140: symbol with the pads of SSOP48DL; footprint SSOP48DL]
Designator prefix IC

## AFE1103E (MF: TEXAS INSTRUMENT CONNECTORS; MPN: AFE1103E; OC_FARNELL: 1509833; OC_NEWARK: 74C7270)  [SSOP48DL]
1  PGND  pwr
2  PVDD  pwr
3  TXCLK  in
4  TXDN  in
5  TXDP  in
6  RXD0  out
7  RXD1  out
8  RXD2  out
9  RXD3  out
10  RXD4  out
11  RXD5  out
12  DGND  pwr
13  DVDD  pwr
14  RXD6  out
15  RXD7  out
16  RXD8  out
17  RXD9  out
18  RXD10  out
19  RXD11  out
20  RXD12  out
21  RXD13  out
22  DGND  pwr
23  RXSYNC  in
24  RXGAIN0  in
25  RXGAIN1  in
26  RXLOOP  in
27  AVDD  pwr
28  RXHYBN  in
29  RXHYBP  in
30  TXLN  out
31  RXLP  in
32  AGND  pwr
33  AGND  pwr
34  REFP  out
35  VCM  out
36  REFN  out
37  AVDD  pwr
38  AGND  pwr
39  RXLN  in
40  AVDD  pwr
41  TXLP  out
42  AGND  pwr
43  NC  nc
44  NC  nc
45  NC  nc
46  NC  nc
47  PLLOUT  out
48  PLLIN  in

## Footprint SSOP48DL (pad centres in mm)
Small Shrink Outline Package
smd 0.305 x 1.397: 1 -7.303,-4.483; 2 -6.668,-4.483; 3 -6.032,-4.483; 4 -5.397,-4.483; 5 -4.763,-4.483; 6 -4.128,-4.483; 7 -3.493,-4.483; 8 -2.857,-4.483; 9 -2.223,-4.483; 10 -1.587,-4.483; 11 -0.953,-4.483; 12 -0.318,-4.483; 13 0.318,-4.483; 14 0.953,-4.483; 15 1.587,-4.483; 16 2.223,-4.483; 17 2.857,-4.483; 18 3.493,-4.483; 19 4.128,-4.483; 20 4.763,-4.483; 21 5.397,-4.483; 22 6.032,-4.483; 23 6.668,-4.483; 24 7.303,-4.483; 25 7.303,4.483; 26 6.668,4.483; 27 6.032,4.483; 28 5.397,4.483; 29 4.763,4.483; 30 4.128,4.483; 31 3.493,4.483; 32 2.857,4.483; 33 2.223,4.483; 34 1.587,4.483; 35 0.953,4.483; 36 0.318,4.483; 37 -0.318,4.483; 38 -0.953,4.483; 39 -1.587,4.483; 40 -2.223,4.483; 41 -2.857,4.483; 42 -3.493,4.483; 43 -4.128,4.483; 44 -4.763,4.483; 45 -5.397,4.483; 46 -6.032,4.483; 47 -6.668,4.483; 48 -7.303,4.483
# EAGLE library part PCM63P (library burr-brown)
Colinear 20-Bit Monolithic Audio DAC

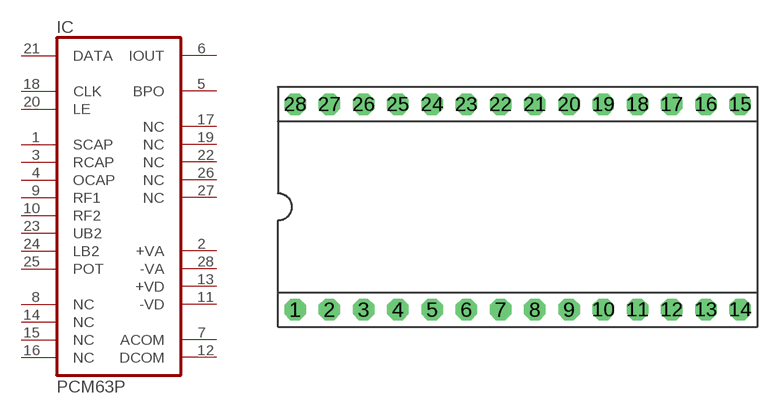
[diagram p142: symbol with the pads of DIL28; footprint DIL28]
Designator prefix IC

## PCM63P (OC_FARNELL: unknown; OC_NEWARK: unknown)  [DIL28]
1  SCAP  pas
2  +VA  pwr
3  RCAP  pas
4  OCAP  pas
5  BPO  out
6  IOUT  out
7  ACOM  pwr
8  NC  nc
9  RF1  pas
10  RF2  pas
11  -VD  pwr
12  DCOM  pwr
13  +VD  pwr
14  NC  nc
15  NC  nc
16  NC  nc
17  NC  nc
18  CLK  in
19  NC  nc
20  LE  in
21  DATA  in
22  NC  nc
23  UB2  pas
24  LB2  pas
25  POT  pas
26  NC  nc
27  NC  nc
28  -VA  pwr

## Footprint DIL28 (pad centres in mm)
Dual In Line
drill 0.813 pad 1.6 octagon: 1 -16.51,-7.62; 2 -13.97,-7.62; 3 -11.43,-7.62; 4 -8.89,-7.62; 5 -6.35,-7.62; 6 -3.81,-7.62; 7 -1.27,-7.62; 8 1.27,-7.62; 9 3.81,-7.62; 10 6.35,-7.62; 11 8.89,-7.62; 12 11.43,-7.62; 13 13.97,-7.62; 14 16.51,-7.62; 15 16.51,7.62; 16 13.97,7.62; 17 11.43,7.62; 18 8.89,7.62; 19 6.35,7.62; 20 3.81,7.62; 21 1.27,7.62; 22 -1.27,7.62; 23 -3.81,7.62; 24 -6.35,7.62; 25 -8.89,7.62; 26 -11.43,7.62; 27 -13.97,7.62; 28 -16.51,7.62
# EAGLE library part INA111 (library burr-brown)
Instrumentation Amplifier High Speed FET-Input

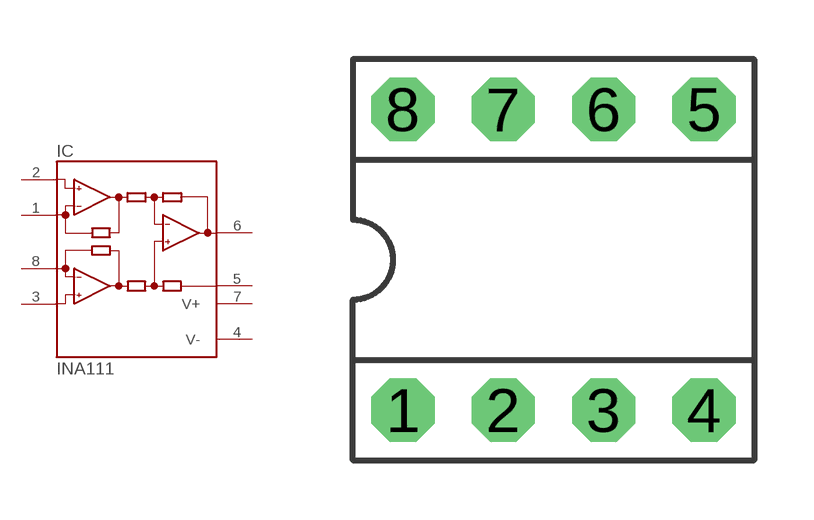
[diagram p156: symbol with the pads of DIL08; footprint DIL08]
Designator prefix IC

## INA111P (MF: TEXAS INSTRUMENT CONNECTORS; MPN: INA111BP; OC_FARNELL: 1212397; OC_NEWARK: 27C4351)  [DIL08]
1  RG  pas
2  -IN  in
3  +IN  in
4  V-  pwr
5  REF  pas
6  OUT  out
7  V+  pwr
8  RG  pas

## Footprint DIL08 (pad centres in mm)
Dual In Line
drill 0.813 pad 1.6 octagon: 1 -3.81,-3.81; 2 -1.27,-3.81; 3 1.27,-3.81; 4 3.81,-3.81; 5 3.81,3.81; 6 1.27,3.81; 7 -1.27,3.81; 8 -3.81,3.81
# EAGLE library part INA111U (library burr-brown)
Precision Instrumentation Amplifier

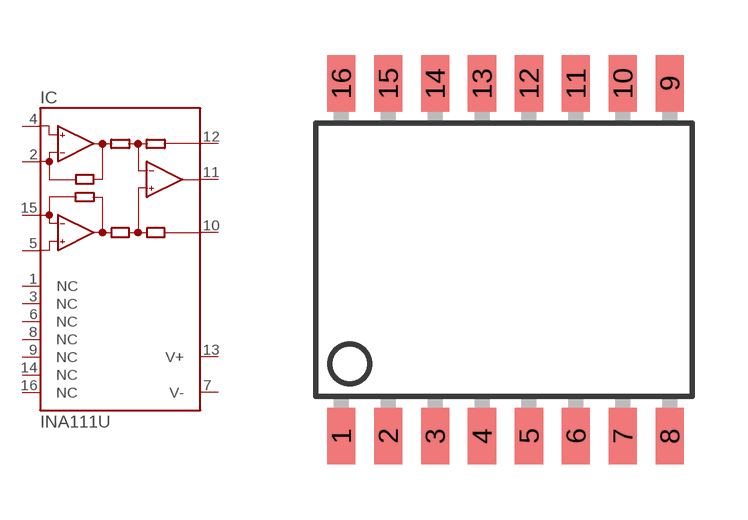
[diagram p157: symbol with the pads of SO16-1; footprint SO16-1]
Designator prefix IC

## INA111U (MF: TEXAS INSTRUMENT CONNECTORS; MPN: INA111BP; OC_FARNELL: 1212397; OC_NEWARK: 27C4351)  [SO16-1]
1  NC  nc
2  RG  pas
3  NC  nc
4  -IN  in
5  +IN  in
6  NC  nc
7  V-  pwr
8  NC  nc
9  NC  nc
10  REF  pas
11  OUT  out
12  FB  pas
13  V+  pwr
14  NC  nc
15  RG  pas
16  NC  nc

## Footprint SO16-1 (pad centres in mm)
Small Outline Package
smd 0.762 x 1.524: 1 -4.445,-4.775; 2 -3.175,-4.775; 3 -1.905,-4.775; 4 -0.635,-4.775; 5 0.635,-4.775; 6 1.905,-4.775; 7 3.175,-4.775; 8 4.445,-4.775; 9 4.445,4.775; 10 3.175,4.775; 11 1.905,4.775; 12 0.635,4.775; 13 -0.635,4.775; 14 -1.905,4.775; 15 -3.175,4.775; 16 -4.445,4.775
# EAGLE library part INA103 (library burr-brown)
Instrumentation Amplifier Low Distortion, Low Noise

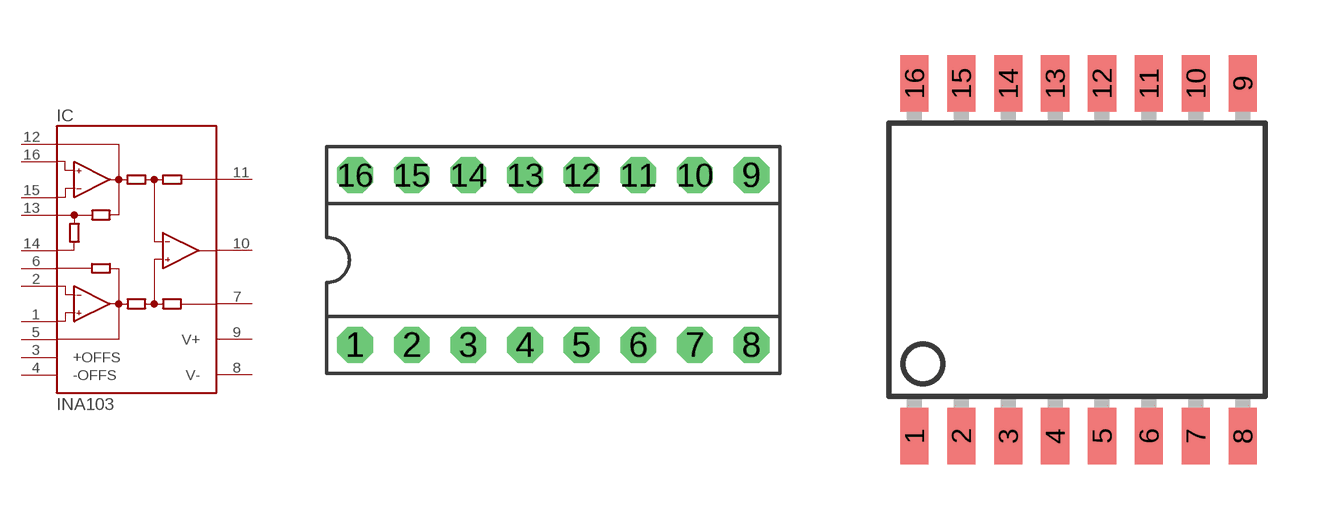
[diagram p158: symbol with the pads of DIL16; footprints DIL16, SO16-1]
Designator prefix IC

## INA103P (MF: TEXAS INSTRUMENTS; MPN: INA103KP; OC_FARNELL: 1212392; OC_NEWARK: 74K3805)  [DIL16]
1  +IN  in
2  +GS  in
3  +OFFS  pas
4  -OFFS  pas
5  +GD  pas
6  +RG  pas
7  REF  pas
8  V-  pwr
9  V+  pwr
10  OUT  out
11  SENSE  in
12  -GD  pas
13  -RG  pas
14  G=100  pas
15  -GS  in
16  -IN  in

## INA103U (MF: TEXAS INSTRUMENTS; MPN: INA103KU; OC_FARNELL: 1212393; OC_NEWARK: 35C1712)  [SO16-1]
Pads as for DIL16

## Footprint DIL16 (pad centres in mm)
Dual In Line
drill 0.813 pad 1.6 octagon: 1 -8.89,-3.81; 2 -6.35,-3.81; 3 -3.81,-3.81; 4 -1.27,-3.81; 5 1.27,-3.81; 6 3.81,-3.81; 7 6.35,-3.81; 8 8.89,-3.81; 9 8.89,3.81; 10 6.35,3.81; 11 3.81,3.81; 12 1.27,3.81; 13 -1.27,3.81; 14 -3.81,3.81; 15 -6.35,3.81; 16 -8.89,3.81

## Footprint SO16-1 (pad centres in mm)
Small Outline Package
smd 0.762 x 1.524: 1 -4.445,-4.775; 2 -3.175,-4.775; 3 -1.905,-4.775; 4 -0.635,-4.775; 5 0.635,-4.775; 6 1.905,-4.775; 7 3.175,-4.775; 8 4.445,-4.775; 9 4.445,4.775; 10 3.175,4.775; 11 1.905,4.775; 12 0.635,4.775; 13 -0.635,4.775; 14 -1.905,4.775; 15 -3.175,4.775; 16 -4.445,4.775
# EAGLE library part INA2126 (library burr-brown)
Instrumentation Amplifier Micropower, Single and Dual Versions Source: http://focus.ti.com/lit/ds/symlink/ina2126.pdf

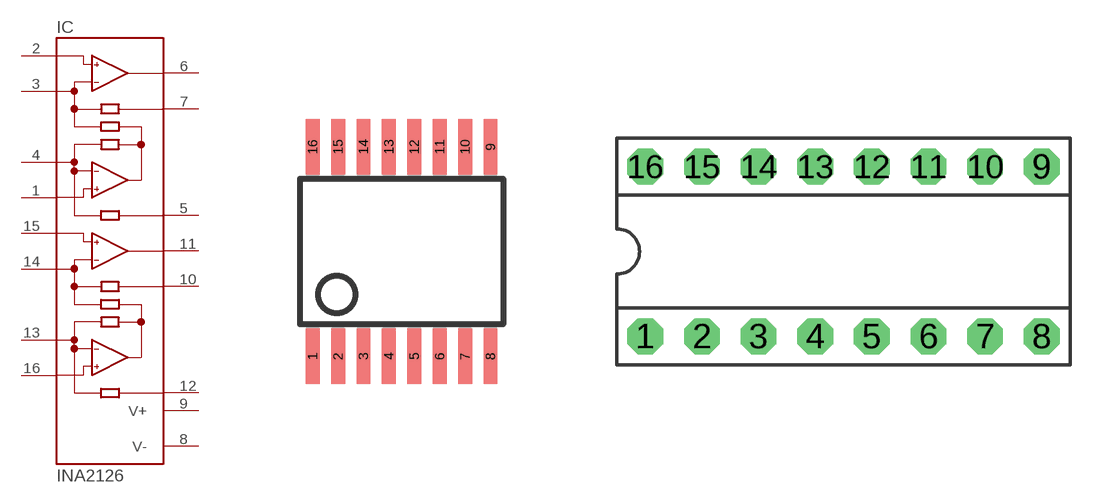
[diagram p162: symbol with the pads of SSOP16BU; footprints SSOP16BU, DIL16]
Designator prefix IC

## INA2126E (MPN: INA2126UAE4; OC_FARNELL: 1234796; OC_NEWARK: 13M1604)  [SSOP16BU]
1  -INA  in
2  +INA  in
3  RGA  pas
4  RGA  pas
5  REFA  pwr
6  OUTA  out
7  SENSEA  pas
8  V-  pwr
9  V+  pwr
10  SENSEB  pas
11  OUTB  out
12  REFB  pwr
13  RGB  pas
14  RGB  pas
15  +INB  in
16  -INB  in

## INA2126P (MF: TEXAS INSTRUMENT CONNECTORS; MPN: INA2126P; OC_FARNELL: 1535404; OC_NEWARK: 74C9838)  [DIL16]
Pads as for SSOP16BU

## INA2126U (MF: TEXAS INSTRUMENT CONNECTORS; MPN: INA2126U; OC_FARNELL: 1459464; OC_NEWARK: 74C9839)  [SO16]
Pads as for SSOP16BU

## Footprint SSOP16BU (pad centres in mm)
Small Shrink Outline Package Source: http://focus.ti.com/lit/ml/msoi004e/msoi004e.pdf
smd 0.348 x 1.397: 1 -2.223,-2.619; 2 -1.588,-2.62; 3 -0.953,-2.62; 4 -0.318,-2.62; 5 0.318,-2.62; 6 0.953,-2.62; 7 1.588,-2.62; 8 2.223,-2.62; 9 2.223,2.62; 10 1.588,2.62; 11 0.953,2.62; 12 0.318,2.62; 13 -0.318,2.62; 14 -0.953,2.62; 15 -1.588,2.62; 16 -2.223,2.62

## Footprint DIL16 (pad centres in mm)
Dual In Line
drill 0.813 pad 1.6 octagon: 1 -8.89,-3.81; 2 -6.35,-3.81; 3 -3.81,-3.81; 4 -1.27,-3.81; 5 1.27,-3.81; 6 3.81,-3.81; 7 6.35,-3.81; 8 8.89,-3.81; 9 8.89,3.81; 10 6.35,3.81; 11 3.81,3.81; 12 1.27,3.81; 13 -1.27,3.81; 14 -3.81,3.81; 15 -6.35,3.81; 16 -8.89,3.81

## Footprint SO16 (pad centres in mm)
PLASTIC SMALL-OUTLINES PACKAGE D (R-PDSO-G16) Source: http://focus.ti.com/lit/ds/symlink/ina2126.pdf
smd 0.762 x 1.524: 1 -4.445,-2.875; 2 -3.175,-2.875; 3 -1.905,-2.875; 4 -0.635,-2.875; 5 0.635,-2.875; 6 1.905,-2.875; 7 3.175,-2.875; 8 4.445,-2.875; 9 4.445,2.875; 10 3.175,2.875; 11 1.905,2.875; 12 0.635,2.875; 13 -0.635,2.875; 14 -1.905,2.875; 15 -3.175,2.875; 16 -4.445,2.875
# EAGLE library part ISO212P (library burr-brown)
Isolated DC/DC Amplifier

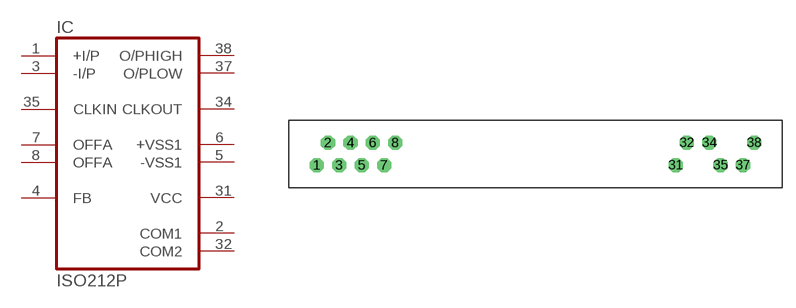
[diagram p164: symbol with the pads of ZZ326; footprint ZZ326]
Designator prefix IC

## ISO212P (OC_FARNELL: unknown; OC_NEWARK: unknown)  [ZZ326]
1  +I/P  in
2  COM1  pwr
3  -I/P  in
4  FB  pas
5  -VSS1  out
6  +VSS1  out
7  OFFA  pas
8  OFFA  pas
31  VCC  pwr
32  COM2  pwr
34  CLKOUT  out
35  CLKIN  in
37  O/PLOW  out
38  O/PHIGH  out

## Footprint ZZ326 (pad centres in mm)
Special Package
drill 0.813 pad 1.6 octagon: 1 -26.67,-1.27; 2 -25.4,1.27; 3 -24.13,-1.27; 4 -22.86,1.27; 5 -21.59,-1.27; 6 -20.32,1.27; 7 -19.05,-1.27; 8 -17.78,1.27; 31 13.97,-1.27; 32 15.24,1.27; 34 17.78,1.27; 35 19.05,-1.27; 37 21.59,-1.27; 38 22.86,1.27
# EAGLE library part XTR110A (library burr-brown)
Precision Voltage-To-Current Converter/Transmitter

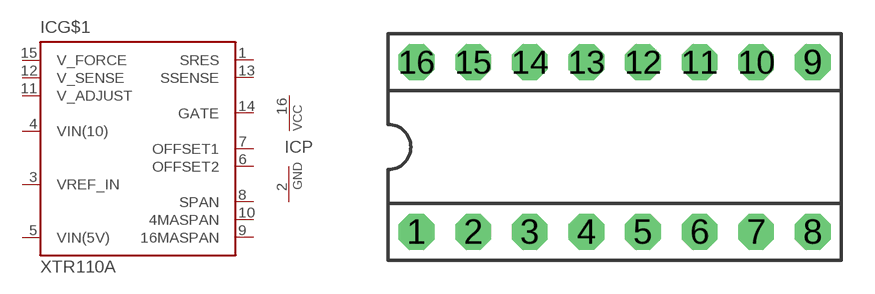
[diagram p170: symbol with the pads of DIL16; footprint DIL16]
Designator prefix IC; gates G$1=XTR110A P=PWRN

## XTR110A (MF: TEXAS INSTRUMENT CONNECTORS; MPN: XTR110AG; OC_FARNELL: 1652416; OC_NEWARK: 04M4626)  [DIL16]
1  G$1:SRES  pas
2  P:GND  pwr
3  G$1:VREF_IN  pas
4  G$1:VIN(10)  pas
5  G$1:VIN(5V)  pas
6  G$1:OFFSET2  pas
7  G$1:OFFSET1  pas
8  G$1:SPAN  pas
9  G$1:16MASPAN  pas
10  G$1:4MASPAN  pas
11  G$1:V_ADJUST  pas
12  G$1:V_SENSE  pas
13  G$1:SSENSE  pas
14  G$1:GATE  pas
15  G$1:V_FORCE  pas
16  P:VCC  pwr

## Footprint DIL16 (pad centres in mm)
Dual In Line
drill 0.813 pad 1.6 octagon: 1 -8.89,-3.81; 2 -6.35,-3.81; 3 -3.81,-3.81; 4 -1.27,-3.81; 5 1.27,-3.81; 6 3.81,-3.81; 7 6.35,-3.81; 8 8.89,-3.81; 9 8.89,3.81; 10 6.35,3.81; 11 3.81,3.81; 12 1.27,3.81; 13 -1.27,3.81; 14 -3.81,3.81; 15 -6.35,3.81; 16 -8.89,3.81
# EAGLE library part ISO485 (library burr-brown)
Isolated RS-485 Differential Bus Transceiver

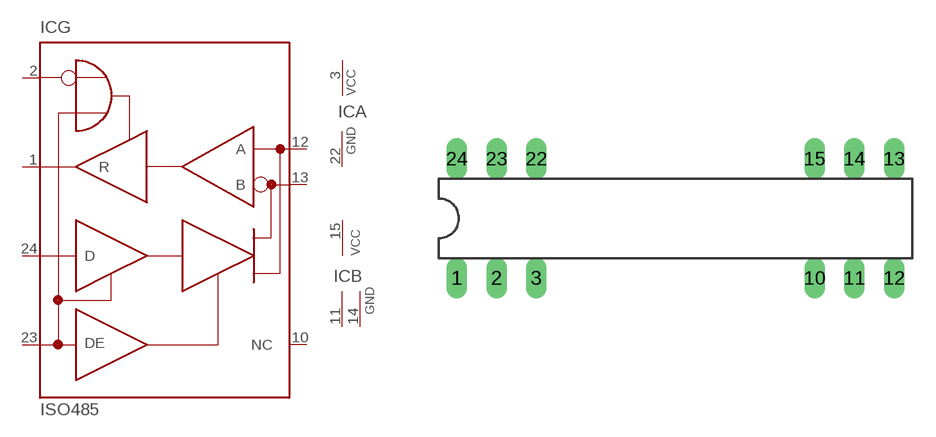
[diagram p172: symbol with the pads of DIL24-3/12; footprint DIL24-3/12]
Designator prefix IC; gates G=ISO485P A=PWRN B=PWR2

## ISO485P (OC_FARNELL: unknown; OC_NEWARK: unknown)  [DIL24-3/12]
1  G:R  in
2  G:RE  in
3  A:VCC  pwr
10  G:NC  nc
11  B:GND  pwr
12  G:A
13  G:B
14  B:GND  pwr
15  B:VCC  pwr
22  A:GND  pwr
23  G:DE  in
24  G:D  out

## Footprint DIL24-3/12 (pad centres in mm)
Dual In Line 0.3 inch
drill 0.813 long: 1 -13.97,-3.81; 2 -11.43,-3.81; 3 -8.89,-3.81; 10 8.89,-3.81; 11 11.43,-3.81; 12 13.97,-3.81; 13 13.97,3.81; 14 11.43,3.81; 15 8.89,3.81; 22 -8.89,3.81; 23 -11.43,3.81; 24 -13.97,3.81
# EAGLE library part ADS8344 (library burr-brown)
16-Bit, 8-Channel Serial Output Sampling ADC

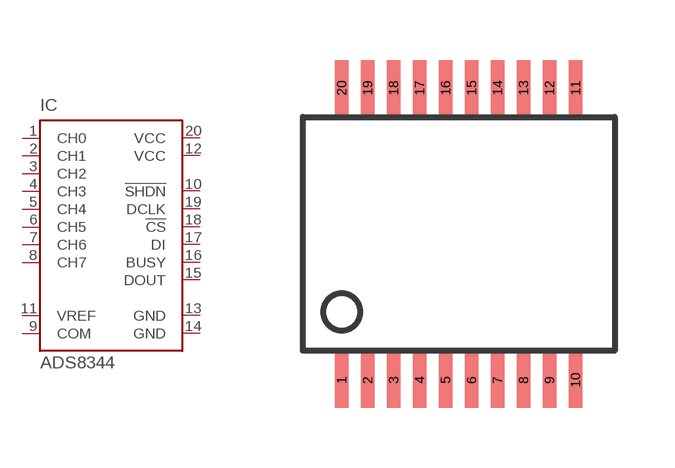
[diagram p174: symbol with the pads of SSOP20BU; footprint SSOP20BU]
Designator prefix IC

## ADS8344U (MPN: ADS8344NB; OC_FARNELL: 1212294; OC_NEWARK: 01M6827)  [SSOP20BU]
1  CH0  in
2  CH1  in
3  CH2  in
4  CH3  in
5  CH4  in
6  CH5  in
7  CH6  in
8  CH7  in
9  COM  in
10  !SHDN  in
11  VREF  in
12  VCC  pwr
13  GND  pwr
14  GND  pwr
15  DOUT  out
16  BUSY  out
17  DI  in
18  !CS  in
19  DCLK  in
20  VCC  pwr

## Footprint SSOP20BU (pad centres in mm)
Small Shrink Outline Package
smd 0.348 x 1.397: 1 -2.925,-3.656; 2 -2.275,-3.656; 3 -1.625,-3.656; 4 -0.975,-3.656; 5 -0.325,-3.656; 6 0.325,-3.656; 7 0.975,-3.656; 8 1.625,-3.656; 9 2.275,-3.656; 10 2.925,-3.656; 11 2.925,3.656; 12 2.275,3.656; 13 1.625,3.656; 14 0.975,3.656; 15 0.325,3.656; 16 -0.325,3.656; 17 -0.975,3.656; 18 -1.625,3.656; 19 -2.275,3.656; 20 -2.925,3.656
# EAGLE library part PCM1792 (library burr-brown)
AUDIO STEREO DIGITAL-TO-ANALOG CONVERTER 24-BIT, 192-kHz SAMPLING, ADVANCED SEGMENT Source: http://focus.ti.com/lit/ds/symlink/pcm1792.pdf

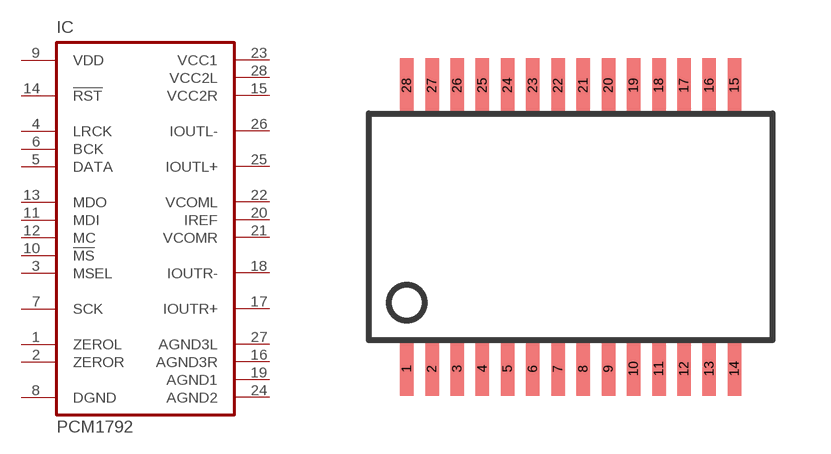
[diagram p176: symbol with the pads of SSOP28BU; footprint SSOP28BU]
Designator prefix IC

## PCM1792 (MPN: PCM1792DBG4; OC_FARNELL: 1408321; OC_NEWARK: 06M7578)  [SSOP28BU]
1  ZEROL  out
2  ZEROR  out
3  MSEL  in
4  LRCK  in
5  DATA  in
6  BCK  in
7  SCK  in
8  DGND  pwr
9  VDD  pwr
10  !MS  in
11  MDI  in
12  MC  in
13  MDO  out
14  !RST  in
15  VCC2R  pwr
16  AGND3R  pwr
17  IOUTR+  out
18  IOUTR-  out
19  AGND1  pwr
20  IREF  pas
21  VCOMR  pas
22  VCOML  pas
23  VCC1  pwr
24  AGND2  pwr
25  IOUTL+  out
26  IOUTL-  out
27  AGND3L  pwr
28  VCC2L  pwr

## Footprint SSOP28BU (pad centres in mm)
Small Shrink Outline Package
smd 0.348 x 1.397: 1 -4.225,-3.656; 2 -3.575,-3.656; 3 -2.925,-3.656; 4 -2.275,-3.656; 5 -1.625,-3.656; 6 -0.975,-3.656; 7 -0.325,-3.656; 8 0.325,-3.656; 9 0.975,-3.656; 10 1.625,-3.656; 11 2.275,-3.656; 12 2.925,-3.656; 13 3.575,-3.656; 14 4.225,-3.656; 15 4.225,3.656; 16 3.575,3.656; 17 2.925,3.656; 18 2.275,3.656; 19 1.625,3.656; 20 0.975,3.656; 21 0.325,3.656; 22 -0.325,3.656; 23 -0.975,3.656; 24 -1.625,3.656; 25 -2.275,3.656; 26 -2.925,3.656; 27 -3.575,3.656; 28 -4.225,3.656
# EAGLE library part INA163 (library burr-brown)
Low-Noise, Low-Distortion INSTRUMENTATION AMPLIFIER Source: http://focus.ti.com/lit/ds/symlink/ina163.pdf

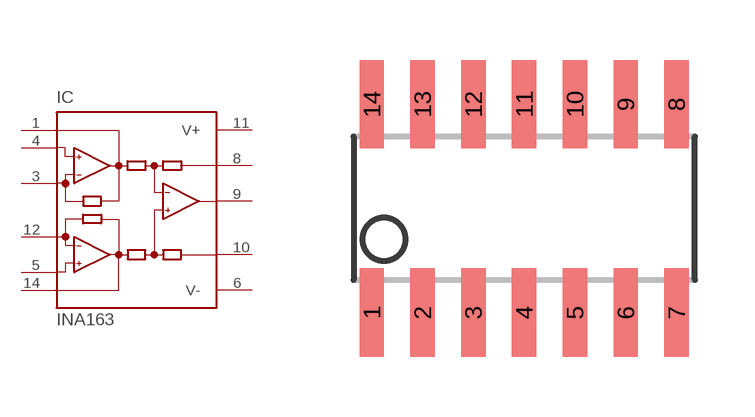
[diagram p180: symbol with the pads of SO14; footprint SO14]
Designator prefix IC

## INA163 (MPN: INA163UAE4; OC_FARNELL: 1206906; OC_NEWARK: 97K1930)  [SO14]
1  VO1  pas
3  GS1  pas
4  -IN  in
5  +IN  in
6  V-  pwr
8  SENSE  pas
9  OUT  out
10  REF  pas
11  V+  pwr
12  GS2  pas
14  VO2  pas

## Footprint SO14 (pad centres in mm)
Small Outline Package
smd 0.61 x 2.21: 1 -3.81,-2.603; 2 -2.54,-2.603; 3 -1.27,-2.603; 4 0,-2.603; 5 1.27,-2.603; 6 2.54,-2.603; 7 3.81,-2.603; 8 3.81,2.603; 9 2.54,2.603; 10 1.27,2.603; 11 0,2.603; 12 -1.27,2.603; 13 -2.54,2.603; 14 -3.81,2.603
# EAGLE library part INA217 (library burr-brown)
Low-Noise, Low-Distortion INSTRUMENTATION AMPLIFIER Replacement for SSM2017 Source: http://focus.ti.com/lit/ds/symlink/ina217.pdf

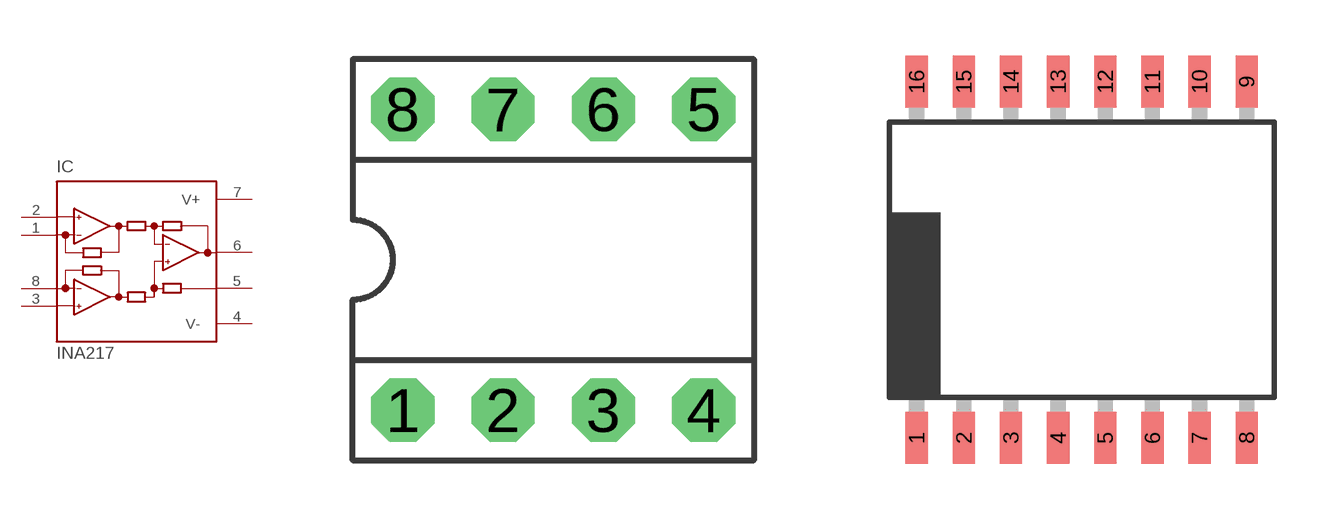
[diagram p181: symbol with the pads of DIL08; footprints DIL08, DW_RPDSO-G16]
Designator prefix IC

## INA217P (MF: TEXAS INSTRUMENTS; MPN: INA217AIP; OC_FARNELL: 1212423; OC_NEWARK: 74C9859)  [DIL08]
1  RG1  pas
2  -IN  in
3  +IN  in
4  V-  pwr
5  REF  pas
6  OUT  out
7  V+  pwr
8  RG2  pas

## INA217DW (MF: TEXAS INSTRUMENTS; MPN: INA217AIDWT; OC_FARNELL: 1459470; OC_NEWARK: 02E2758)  [DW_RPDSO-G16]
2  RG1  pas
4  -IN  in
5  +IN  in
7  V-  pwr
10  REF  pas
11  OUT  out
13  V+  pwr
15  RG2  pas

## Footprint DIL08 (pad centres in mm)
Dual In Line
drill 0.813 pad 1.6 octagon: 1 -3.81,-3.81; 2 -1.27,-3.81; 3 1.27,-3.81; 4 3.81,-3.81; 5 3.81,3.81; 6 1.27,3.81; 7 -1.27,3.81; 8 -3.81,3.81

## Footprint DW_RPDSO-G16 (pad centres in mm)
DW (R-PDSO-G16) SOurce: http://focus.ti.com/lit/ds/symlink/ina217.pdf
smd 0.6 x 1.4: 1 -4.445,-4.8; 2 -3.175,-4.8; 3 -1.905,-4.8; 4 -0.635,-4.8; 5 0.635,-4.8; 6 1.905,-4.8; 7 3.175,-4.8; 8 4.445,-4.8; 9 4.445,4.8; 10 3.175,4.8; 11 1.905,4.8; 12 0.635,4.8; 13 -0.635,4.8; 14 -1.905,4.8; 15 -3.175,4.8; 16 -4.445,4.8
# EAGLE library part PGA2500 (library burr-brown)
Digitally Controlled Microphone Preamplifier Source: http://focus.ti.com/lit/ds/symlink/pga2500.pdf

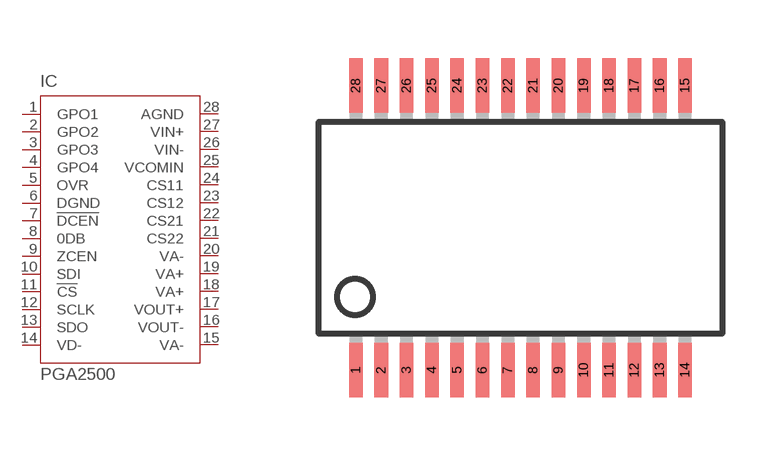
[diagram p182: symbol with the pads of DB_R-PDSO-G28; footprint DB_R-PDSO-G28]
Designator prefix IC

## PGA2500DB (OC_FARNELL: unknown; OC_NEWARK: unknown)  [DB_R-PDSO-G28]
1  GPO1  out
2  GPO2  out
3  GPO3  out
4  GPO4  out
5  OVR  out
6  DGND  pwr
7  !DCEN  in
8  0DB  in
9  ZCEN  in
10  SDI  in
11  !CS  in
12  SCLK  in
13  SDO  out
14  VD-  pwr
15  VA-  pwr
16  VOUT-  out
17  VOUT+  out
18  VA+  pwr
19  VA+  pwr
20  VA-  pwr
21  CS22  pas
22  CS21  pas
23  CS12  pas
24  CS11  pas
25  VCOMIN  pwr
26  VIN-  in
27  VIN+  in
28  AGND  pwr

## Footprint DB_R-PDSO-G28 (pad centres in mm)
DB (R-PDSO-G28) Source: http://focus.ti.com/lit/ds/symlink/ads1210.pdf
smd 0.348 x 1.397: 1 -4.225,-3.656; 2 -3.575,-3.656; 3 -2.925,-3.656; 4 -2.275,-3.656; 5 -1.625,-3.656; 6 -0.975,-3.656; 7 -0.325,-3.656; 8 0.325,-3.656; 9 0.975,-3.656; 10 1.625,-3.656; 11 2.275,-3.656; 12 2.925,-3.656; 13 3.575,-3.656; 14 4.225,-3.656; 15 4.225,3.656; 16 3.575,3.656; 17 2.925,3.656; 18 2.275,3.656; 19 1.625,3.656; 20 0.975,3.656; 21 0.325,3.656; 22 -0.325,3.656; 23 -0.975,3.656; 24 -1.625,3.656; 25 -2.275,3.656; 26 -2.925,3.656; 27 -3.575,3.656; 28 -4.225,3.656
